VERSION 5.8 ;
BUSBITCHARS "[]" ;
DIVIDERCHAR "/" ;
UNITS
    DATABASE MICRONS 1000 ;
END UNITS

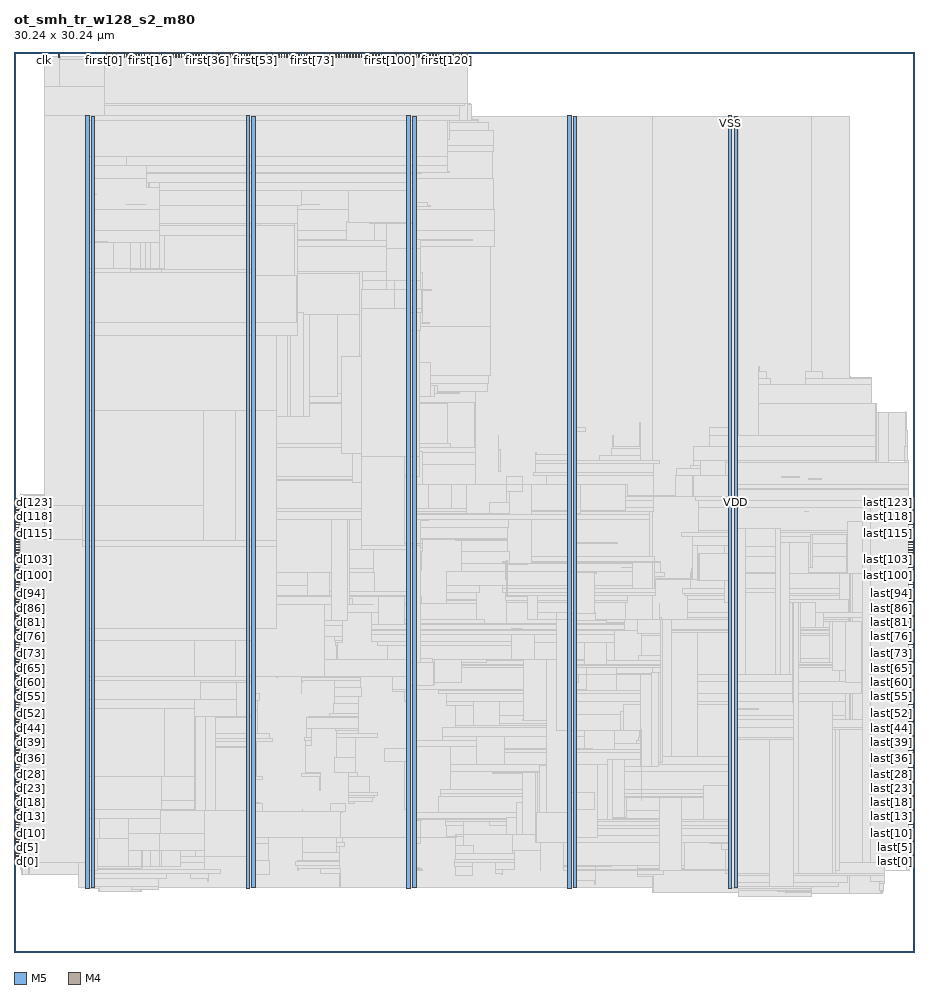
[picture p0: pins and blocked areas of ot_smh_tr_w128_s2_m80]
MACRO ot_smh_tr_w128_s2_m80
  FOREIGN ot_smh_tr_w128_s2_m80 0 0 ;
  CLASS BLOCK ;
  SIZE 30.24 BY 30.24 ;
  PIN clk
    DIRECTION INPUT ;
    USE SIGNAL ;
    PORT
      LAYER M5 ;
        RECT  1.008 30.048 1.032 30.24 ;
    END
  END clk
  PIN d[0]
    DIRECTION INPUT ;
    USE SIGNAL ;
    PORT
      LAYER M4 ;
        RECT  0 3.024 0.192 3.048 ;
    END
  END d[0]
  PIN d[100]
    DIRECTION INPUT ;
    USE SIGNAL ;
    PORT
      LAYER M4 ;
        RECT  0 12.624 0.192 12.648 ;
    END
  END d[100]
  PIN d[101]
    DIRECTION INPUT ;
    USE SIGNAL ;
    PORT
      LAYER M4 ;
        RECT  0 12.72 0.192 12.744 ;
    END
  END d[101]
  PIN d[102]
    DIRECTION INPUT ;
    USE SIGNAL ;
    PORT
      LAYER M4 ;
        RECT  0 12.816 0.192 12.84 ;
    END
  END d[102]
  PIN d[103]
    DIRECTION INPUT ;
    USE SIGNAL ;
    PORT
      LAYER M4 ;
        RECT  0 12.912 0.192 12.936 ;
    END
  END d[103]
  PIN d[104]
    DIRECTION INPUT ;
    USE SIGNAL ;
    PORT
      LAYER M4 ;
        RECT  0 13.008 0.192 13.032 ;
    END
  END d[104]
  PIN d[105]
    DIRECTION INPUT ;
    USE SIGNAL ;
    PORT
      LAYER M4 ;
        RECT  0 13.104 0.192 13.128 ;
    END
  END d[105]
  PIN d[106]
    DIRECTION INPUT ;
    USE SIGNAL ;
    PORT
      LAYER M4 ;
        RECT  0 13.2 0.192 13.224 ;
    END
  END d[106]
  PIN d[107]
    DIRECTION INPUT ;
    USE SIGNAL ;
    PORT
      LAYER M4 ;
        RECT  0 13.296 0.192 13.32 ;
    END
  END d[107]
  PIN d[108]
    DIRECTION INPUT ;
    USE SIGNAL ;
    PORT
      LAYER M4 ;
        RECT  0 13.392 0.192 13.416 ;
    END
  END d[108]
  PIN d[109]
    DIRECTION INPUT ;
    USE SIGNAL ;
    PORT
      LAYER M4 ;
        RECT  0 13.488 0.192 13.512 ;
    END
  END d[109]
  PIN d[10]
    DIRECTION INPUT ;
    USE SIGNAL ;
    PORT
      LAYER M4 ;
        RECT  0 3.984 0.192 4.008 ;
    END
  END d[10]
  PIN d[110]
    DIRECTION INPUT ;
    USE SIGNAL ;
    PORT
      LAYER M4 ;
        RECT  0 13.584 0.192 13.608 ;
    END
  END d[110]
  PIN d[111]
    DIRECTION INPUT ;
    USE SIGNAL ;
    PORT
      LAYER M4 ;
        RECT  0 13.68 0.192 13.704 ;
    END
  END d[111]
  PIN d[112]
    DIRECTION INPUT ;
    USE SIGNAL ;
    PORT
      LAYER M4 ;
        RECT  0 13.776 0.192 13.8 ;
    END
  END d[112]
  PIN d[113]
    DIRECTION INPUT ;
    USE SIGNAL ;
    PORT
      LAYER M4 ;
        RECT  0 13.872 0.192 13.896 ;
    END
  END d[113]
  PIN d[114]
    DIRECTION INPUT ;
    USE SIGNAL ;
    PORT
      LAYER M4 ;
        RECT  0 13.968 0.192 13.992 ;
    END
  END d[114]
  PIN d[115]
    DIRECTION INPUT ;
    USE SIGNAL ;
    PORT
      LAYER M4 ;
        RECT  0 14.064 0.192 14.088 ;
    END
  END d[115]
  PIN d[116]
    DIRECTION INPUT ;
    USE SIGNAL ;
    PORT
      LAYER M4 ;
        RECT  0 14.16 0.192 14.184 ;
    END
  END d[116]
  PIN d[117]
    DIRECTION INPUT ;
    USE SIGNAL ;
    PORT
      LAYER M4 ;
        RECT  0 14.256 0.192 14.28 ;
    END
  END d[117]
  PIN d[118]
    DIRECTION INPUT ;
    USE SIGNAL ;
    PORT
      LAYER M4 ;
        RECT  0 14.352 0.192 14.376 ;
    END
  END d[118]
  PIN d[119]
    DIRECTION INPUT ;
    USE SIGNAL ;
    PORT
      LAYER M4 ;
        RECT  0 14.448 0.192 14.472 ;
    END
  END d[119]
  PIN d[11]
    DIRECTION INPUT ;
    USE SIGNAL ;
    PORT
      LAYER M4 ;
        RECT  0 4.08 0.192 4.104 ;
    END
  END d[11]
  PIN d[120]
    DIRECTION INPUT ;
    USE SIGNAL ;
    PORT
      LAYER M4 ;
        RECT  0 14.544 0.192 14.568 ;
    END
  END d[120]
  PIN d[121]
    DIRECTION INPUT ;
    USE SIGNAL ;
    PORT
      LAYER M4 ;
        RECT  0 14.64 0.192 14.664 ;
    END
  END d[121]
  PIN d[122]
    DIRECTION INPUT ;
    USE SIGNAL ;
    PORT
      LAYER M4 ;
        RECT  0 14.736 0.192 14.76 ;
    END
  END d[122]
  PIN d[123]
    DIRECTION INPUT ;
    USE SIGNAL ;
    PORT
      LAYER M4 ;
        RECT  0 14.832 0.192 14.856 ;
    END
  END d[123]
  PIN d[124]
    DIRECTION INPUT ;
    USE SIGNAL ;
    PORT
      LAYER M4 ;
        RECT  0 14.928 0.192 14.952 ;
    END
  END d[124]
  PIN d[125]
    DIRECTION INPUT ;
    USE SIGNAL ;
    PORT
      LAYER M4 ;
        RECT  0 15.024 0.192 15.048 ;
    END
  END d[125]
  PIN d[126]
    DIRECTION INPUT ;
    USE SIGNAL ;
    PORT
      LAYER M4 ;
        RECT  0 15.12 0.192 15.144 ;
    END
  END d[126]
  PIN d[127]
    DIRECTION INPUT ;
    USE SIGNAL ;
    PORT
      LAYER M4 ;
        RECT  0 15.216 0.192 15.24 ;
    END
  END d[127]
  PIN d[12]
    DIRECTION INPUT ;
    USE SIGNAL ;
    PORT
      LAYER M4 ;
        RECT  0 4.176 0.192 4.2 ;
    END
  END d[12]
  PIN d[13]
    DIRECTION INPUT ;
    USE SIGNAL ;
    PORT
      LAYER M4 ;
        RECT  0 4.272 0.192 4.296 ;
    END
  END d[13]
  PIN d[14]
    DIRECTION INPUT ;
    USE SIGNAL ;
    PORT
      LAYER M4 ;
        RECT  0 4.368 0.192 4.392 ;
    END
  END d[14]
  PIN d[15]
    DIRECTION INPUT ;
    USE SIGNAL ;
    PORT
      LAYER M4 ;
        RECT  0 4.464 0.192 4.488 ;
    END
  END d[15]
  PIN d[16]
    DIRECTION INPUT ;
    USE SIGNAL ;
    PORT
      LAYER M4 ;
        RECT  0 4.56 0.192 4.584 ;
    END
  END d[16]
  PIN d[17]
    DIRECTION INPUT ;
    USE SIGNAL ;
    PORT
      LAYER M4 ;
        RECT  0 4.656 0.192 4.68 ;
    END
  END d[17]
  PIN d[18]
    DIRECTION INPUT ;
    USE SIGNAL ;
    PORT
      LAYER M4 ;
        RECT  0 4.752 0.192 4.776 ;
    END
  END d[18]
  PIN d[19]
    DIRECTION INPUT ;
    USE SIGNAL ;
    PORT
      LAYER M4 ;
        RECT  0 4.848 0.192 4.872 ;
    END
  END d[19]
  PIN d[1]
    DIRECTION INPUT ;
    USE SIGNAL ;
    PORT
      LAYER M4 ;
        RECT  0 3.12 0.192 3.144 ;
    END
  END d[1]
  PIN d[20]
    DIRECTION INPUT ;
    USE SIGNAL ;
    PORT
      LAYER M4 ;
        RECT  0 4.944 0.192 4.968 ;
    END
  END d[20]
  PIN d[21]
    DIRECTION INPUT ;
    USE SIGNAL ;
    PORT
      LAYER M4 ;
        RECT  0 5.04 0.192 5.064 ;
    END
  END d[21]
  PIN d[22]
    DIRECTION INPUT ;
    USE SIGNAL ;
    PORT
      LAYER M4 ;
        RECT  0 5.136 0.192 5.16 ;
    END
  END d[22]
  PIN d[23]
    DIRECTION INPUT ;
    USE SIGNAL ;
    PORT
      LAYER M4 ;
        RECT  0 5.232 0.192 5.256 ;
    END
  END d[23]
  PIN d[24]
    DIRECTION INPUT ;
    USE SIGNAL ;
    PORT
      LAYER M4 ;
        RECT  0 5.328 0.192 5.352 ;
    END
  END d[24]
  PIN d[25]
    DIRECTION INPUT ;
    USE SIGNAL ;
    PORT
      LAYER M4 ;
        RECT  0 5.424 0.192 5.448 ;
    END
  END d[25]
  PIN d[26]
    DIRECTION INPUT ;
    USE SIGNAL ;
    PORT
      LAYER M4 ;
        RECT  0 5.52 0.192 5.544 ;
    END
  END d[26]
  PIN d[27]
    DIRECTION INPUT ;
    USE SIGNAL ;
    PORT
      LAYER M4 ;
        RECT  0 5.616 0.192 5.64 ;
    END
  END d[27]
  PIN d[28]
    DIRECTION INPUT ;
    USE SIGNAL ;
    PORT
      LAYER M4 ;
        RECT  0 5.712 0.192 5.736 ;
    END
  END d[28]
  PIN d[29]
    DIRECTION INPUT ;
    USE SIGNAL ;
    PORT
      LAYER M4 ;
        RECT  0 5.808 0.192 5.832 ;
    END
  END d[29]
  PIN d[2]
    DIRECTION INPUT ;
    USE SIGNAL ;
    PORT
      LAYER M4 ;
        RECT  0 3.216 0.192 3.24 ;
    END
  END d[2]
  PIN d[30]
    DIRECTION INPUT ;
    USE SIGNAL ;
    PORT
      LAYER M4 ;
        RECT  0 5.904 0.192 5.928 ;
    END
  END d[30]
  PIN d[31]
    DIRECTION INPUT ;
    USE SIGNAL ;
    PORT
      LAYER M4 ;
        RECT  0 6 0.192 6.024 ;
    END
  END d[31]
  PIN d[32]
    DIRECTION INPUT ;
    USE SIGNAL ;
    PORT
      LAYER M4 ;
        RECT  0 6.096 0.192 6.12 ;
    END
  END d[32]
  PIN d[33]
    DIRECTION INPUT ;
    USE SIGNAL ;
    PORT
      LAYER M4 ;
        RECT  0 6.192 0.192 6.216 ;
    END
  END d[33]
  PIN d[34]
    DIRECTION INPUT ;
    USE SIGNAL ;
    PORT
      LAYER M4 ;
        RECT  0 6.288 0.192 6.312 ;
    END
  END d[34]
  PIN d[35]
    DIRECTION INPUT ;
    USE SIGNAL ;
    PORT
      LAYER M4 ;
        RECT  0 6.384 0.192 6.408 ;
    END
  END d[35]
  PIN d[36]
    DIRECTION INPUT ;
    USE SIGNAL ;
    PORT
      LAYER M4 ;
        RECT  0 6.48 0.192 6.504 ;
    END
  END d[36]
  PIN d[37]
    DIRECTION INPUT ;
    USE SIGNAL ;
    PORT
      LAYER M4 ;
        RECT  0 6.576 0.192 6.6 ;
    END
  END d[37]
  PIN d[38]
    DIRECTION INPUT ;
    USE SIGNAL ;
    PORT
      LAYER M4 ;
        RECT  0 6.672 0.192 6.696 ;
    END
  END d[38]
  PIN d[39]
    DIRECTION INPUT ;
    USE SIGNAL ;
    PORT
      LAYER M4 ;
        RECT  0 6.768 0.192 6.792 ;
    END
  END d[39]
  PIN d[3]
    DIRECTION INPUT ;
    USE SIGNAL ;
    PORT
      LAYER M4 ;
        RECT  0 3.312 0.192 3.336 ;
    END
  END d[3]
  PIN d[40]
    DIRECTION INPUT ;
    USE SIGNAL ;
    PORT
      LAYER M4 ;
        RECT  0 6.864 0.192 6.888 ;
    END
  END d[40]
  PIN d[41]
    DIRECTION INPUT ;
    USE SIGNAL ;
    PORT
      LAYER M4 ;
        RECT  0 6.96 0.192 6.984 ;
    END
  END d[41]
  PIN d[42]
    DIRECTION INPUT ;
    USE SIGNAL ;
    PORT
      LAYER M4 ;
        RECT  0 7.056 0.192 7.08 ;
    END
  END d[42]
  PIN d[43]
    DIRECTION INPUT ;
    USE SIGNAL ;
    PORT
      LAYER M4 ;
        RECT  0 7.152 0.192 7.176 ;
    END
  END d[43]
  PIN d[44]
    DIRECTION INPUT ;
    USE SIGNAL ;
    PORT
      LAYER M4 ;
        RECT  0 7.248 0.192 7.272 ;
    END
  END d[44]
  PIN d[45]
    DIRECTION INPUT ;
    USE SIGNAL ;
    PORT
      LAYER M4 ;
        RECT  0 7.344 0.192 7.368 ;
    END
  END d[45]
  PIN d[46]
    DIRECTION INPUT ;
    USE SIGNAL ;
    PORT
      LAYER M4 ;
        RECT  0 7.44 0.192 7.464 ;
    END
  END d[46]
  PIN d[47]
    DIRECTION INPUT ;
    USE SIGNAL ;
    PORT
      LAYER M4 ;
        RECT  0 7.536 0.192 7.56 ;
    END
  END d[47]
  PIN d[48]
    DIRECTION INPUT ;
    USE SIGNAL ;
    PORT
      LAYER M4 ;
        RECT  0 7.632 0.192 7.656 ;
    END
  END d[48]
  PIN d[49]
    DIRECTION INPUT ;
    USE SIGNAL ;
    PORT
      LAYER M4 ;
        RECT  0 7.728 0.192 7.752 ;
    END
  END d[49]
  PIN d[4]
    DIRECTION INPUT ;
    USE SIGNAL ;
    PORT
      LAYER M4 ;
        RECT  0 3.408 0.192 3.432 ;
    END
  END d[4]
  PIN d[50]
    DIRECTION INPUT ;
    USE SIGNAL ;
    PORT
      LAYER M4 ;
        RECT  0 7.824 0.192 7.848 ;
    END
  END d[50]
  PIN d[51]
    DIRECTION INPUT ;
    USE SIGNAL ;
    PORT
      LAYER M4 ;
        RECT  0 7.92 0.192 7.944 ;
    END
  END d[51]
  PIN d[52]
    DIRECTION INPUT ;
    USE SIGNAL ;
    PORT
      LAYER M4 ;
        RECT  0 8.016 0.192 8.04 ;
    END
  END d[52]
  PIN d[53]
    DIRECTION INPUT ;
    USE SIGNAL ;
    PORT
      LAYER M4 ;
        RECT  0 8.112 0.192 8.136 ;
    END
  END d[53]
  PIN d[54]
    DIRECTION INPUT ;
    USE SIGNAL ;
    PORT
      LAYER M4 ;
        RECT  0 8.208 0.192 8.232 ;
    END
  END d[54]
  PIN d[55]
    DIRECTION INPUT ;
    USE SIGNAL ;
    PORT
      LAYER M4 ;
        RECT  0 8.304 0.192 8.328 ;
    END
  END d[55]
  PIN d[56]
    DIRECTION INPUT ;
    USE SIGNAL ;
    PORT
      LAYER M4 ;
        RECT  0 8.4 0.192 8.424 ;
    END
  END d[56]
  PIN d[57]
    DIRECTION INPUT ;
    USE SIGNAL ;
    PORT
      LAYER M4 ;
        RECT  0 8.496 0.192 8.52 ;
    END
  END d[57]
  PIN d[58]
    DIRECTION INPUT ;
    USE SIGNAL ;
    PORT
      LAYER M4 ;
        RECT  0 8.592 0.192 8.616 ;
    END
  END d[58]
  PIN d[59]
    DIRECTION INPUT ;
    USE SIGNAL ;
    PORT
      LAYER M4 ;
        RECT  0 8.688 0.192 8.712 ;
    END
  END d[59]
  PIN d[5]
    DIRECTION INPUT ;
    USE SIGNAL ;
    PORT
      LAYER M4 ;
        RECT  0 3.504 0.192 3.528 ;
    END
  END d[5]
  PIN d[60]
    DIRECTION INPUT ;
    USE SIGNAL ;
    PORT
      LAYER M4 ;
        RECT  0 8.784 0.192 8.808 ;
    END
  END d[60]
  PIN d[61]
    DIRECTION INPUT ;
    USE SIGNAL ;
    PORT
      LAYER M4 ;
        RECT  0 8.88 0.192 8.904 ;
    END
  END d[61]
  PIN d[62]
    DIRECTION INPUT ;
    USE SIGNAL ;
    PORT
      LAYER M4 ;
        RECT  0 8.976 0.192 9 ;
    END
  END d[62]
  PIN d[63]
    DIRECTION INPUT ;
    USE SIGNAL ;
    PORT
      LAYER M4 ;
        RECT  0 9.072 0.192 9.096 ;
    END
  END d[63]
  PIN d[64]
    DIRECTION INPUT ;
    USE SIGNAL ;
    PORT
      LAYER M4 ;
        RECT  0 9.168 0.192 9.192 ;
    END
  END d[64]
  PIN d[65]
    DIRECTION INPUT ;
    USE SIGNAL ;
    PORT
      LAYER M4 ;
        RECT  0 9.264 0.192 9.288 ;
    END
  END d[65]
  PIN d[66]
    DIRECTION INPUT ;
    USE SIGNAL ;
    PORT
      LAYER M4 ;
        RECT  0 9.36 0.192 9.384 ;
    END
  END d[66]
  PIN d[67]
    DIRECTION INPUT ;
    USE SIGNAL ;
    PORT
      LAYER M4 ;
        RECT  0 9.456 0.192 9.48 ;
    END
  END d[67]
  PIN d[68]
    DIRECTION INPUT ;
    USE SIGNAL ;
    PORT
      LAYER M4 ;
        RECT  0 9.552 0.192 9.576 ;
    END
  END d[68]
  PIN d[69]
    DIRECTION INPUT ;
    USE SIGNAL ;
    PORT
      LAYER M4 ;
        RECT  0 9.648 0.192 9.672 ;
    END
  END d[69]
  PIN d[6]
    DIRECTION INPUT ;
    USE SIGNAL ;
    PORT
      LAYER M4 ;
        RECT  0 3.6 0.192 3.624 ;
    END
  END d[6]
  PIN d[70]
    DIRECTION INPUT ;
    USE SIGNAL ;
    PORT
      LAYER M4 ;
        RECT  0 9.744 0.192 9.768 ;
    END
  END d[70]
  PIN d[71]
    DIRECTION INPUT ;
    USE SIGNAL ;
    PORT
      LAYER M4 ;
        RECT  0 9.84 0.192 9.864 ;
    END
  END d[71]
  PIN d[72]
    DIRECTION INPUT ;
    USE SIGNAL ;
    PORT
      LAYER M4 ;
        RECT  0 9.936 0.192 9.96 ;
    END
  END d[72]
  PIN d[73]
    DIRECTION INPUT ;
    USE SIGNAL ;
    PORT
      LAYER M4 ;
        RECT  0 10.032 0.192 10.056 ;
    END
  END d[73]
  PIN d[74]
    DIRECTION INPUT ;
    USE SIGNAL ;
    PORT
      LAYER M4 ;
        RECT  0 10.128 0.192 10.152 ;
    END
  END d[74]
  PIN d[75]
    DIRECTION INPUT ;
    USE SIGNAL ;
    PORT
      LAYER M4 ;
        RECT  0 10.224 0.192 10.248 ;
    END
  END d[75]
  PIN d[76]
    DIRECTION INPUT ;
    USE SIGNAL ;
    PORT
      LAYER M4 ;
        RECT  0 10.32 0.192 10.344 ;
    END
  END d[76]
  PIN d[77]
    DIRECTION INPUT ;
    USE SIGNAL ;
    PORT
      LAYER M4 ;
        RECT  0 10.416 0.192 10.44 ;
    END
  END d[77]
  PIN d[78]
    DIRECTION INPUT ;
    USE SIGNAL ;
    PORT
      LAYER M4 ;
        RECT  0 10.512 0.192 10.536 ;
    END
  END d[78]
  PIN d[79]
    DIRECTION INPUT ;
    USE SIGNAL ;
    PORT
      LAYER M4 ;
        RECT  0 10.608 0.192 10.632 ;
    END
  END d[79]
  PIN d[7]
    DIRECTION INPUT ;
    USE SIGNAL ;
    PORT
      LAYER M4 ;
        RECT  0 3.696 0.192 3.72 ;
    END
  END d[7]
  PIN d[80]
    DIRECTION INPUT ;
    USE SIGNAL ;
    PORT
      LAYER M4 ;
        RECT  0 10.704 0.192 10.728 ;
    END
  END d[80]
  PIN d[81]
    DIRECTION INPUT ;
    USE SIGNAL ;
    PORT
      LAYER M4 ;
        RECT  0 10.8 0.192 10.824 ;
    END
  END d[81]
  PIN d[82]
    DIRECTION INPUT ;
    USE SIGNAL ;
    PORT
      LAYER M4 ;
        RECT  0 10.896 0.192 10.92 ;
    END
  END d[82]
  PIN d[83]
    DIRECTION INPUT ;
    USE SIGNAL ;
    PORT
      LAYER M4 ;
        RECT  0 10.992 0.192 11.016 ;
    END
  END d[83]
  PIN d[84]
    DIRECTION INPUT ;
    USE SIGNAL ;
    PORT
      LAYER M4 ;
        RECT  0 11.088 0.192 11.112 ;
    END
  END d[84]
  PIN d[85]
    DIRECTION INPUT ;
    USE SIGNAL ;
    PORT
      LAYER M4 ;
        RECT  0 11.184 0.192 11.208 ;
    END
  END d[85]
  PIN d[86]
    DIRECTION INPUT ;
    USE SIGNAL ;
    PORT
      LAYER M4 ;
        RECT  0 11.28 0.192 11.304 ;
    END
  END d[86]
  PIN d[87]
    DIRECTION INPUT ;
    USE SIGNAL ;
    PORT
      LAYER M4 ;
        RECT  0 11.376 0.192 11.4 ;
    END
  END d[87]
  PIN d[88]
    DIRECTION INPUT ;
    USE SIGNAL ;
    PORT
      LAYER M4 ;
        RECT  0 11.472 0.192 11.496 ;
    END
  END d[88]
  PIN d[89]
    DIRECTION INPUT ;
    USE SIGNAL ;
    PORT
      LAYER M4 ;
        RECT  0 11.568 0.192 11.592 ;
    END
  END d[89]
  PIN d[8]
    DIRECTION INPUT ;
    USE SIGNAL ;
    PORT
      LAYER M4 ;
        RECT  0 3.792 0.192 3.816 ;
    END
  END d[8]
  PIN d[90]
    DIRECTION INPUT ;
    USE SIGNAL ;
    PORT
      LAYER M4 ;
        RECT  0 11.664 0.192 11.688 ;
    END
  END d[90]
  PIN d[91]
    DIRECTION INPUT ;
    USE SIGNAL ;
    PORT
      LAYER M4 ;
        RECT  0 11.76 0.192 11.784 ;
    END
  END d[91]
  PIN d[92]
    DIRECTION INPUT ;
    USE SIGNAL ;
    PORT
      LAYER M4 ;
        RECT  0 11.856 0.192 11.88 ;
    END
  END d[92]
  PIN d[93]
    DIRECTION INPUT ;
    USE SIGNAL ;
    PORT
      LAYER M4 ;
        RECT  0 11.952 0.192 11.976 ;
    END
  END d[93]
  PIN d[94]
    DIRECTION INPUT ;
    USE SIGNAL ;
    PORT
      LAYER M4 ;
        RECT  0 12.048 0.192 12.072 ;
    END
  END d[94]
  PIN d[95]
    DIRECTION INPUT ;
    USE SIGNAL ;
    PORT
      LAYER M4 ;
        RECT  0 12.144 0.192 12.168 ;
    END
  END d[95]
  PIN d[96]
    DIRECTION INPUT ;
    USE SIGNAL ;
    PORT
      LAYER M4 ;
        RECT  0 12.24 0.192 12.264 ;
    END
  END d[96]
  PIN d[97]
    DIRECTION INPUT ;
    USE SIGNAL ;
    PORT
      LAYER M4 ;
        RECT  0 12.336 0.192 12.36 ;
    END
  END d[97]
  PIN d[98]
    DIRECTION INPUT ;
    USE SIGNAL ;
    PORT
      LAYER M4 ;
        RECT  0 12.432 0.192 12.456 ;
    END
  END d[98]
  PIN d[99]
    DIRECTION INPUT ;
    USE SIGNAL ;
    PORT
      LAYER M4 ;
        RECT  0 12.528 0.192 12.552 ;
    END
  END d[99]
  PIN d[9]
    DIRECTION INPUT ;
    USE SIGNAL ;
    PORT
      LAYER M4 ;
        RECT  0 3.888 0.192 3.912 ;
    END
  END d[9]
  PIN first[0]
    DIRECTION OUTPUT ;
    USE SIGNAL ;
    PORT
      LAYER M5 ;
        RECT  3.024 30.048 3.048 30.24 ;
    END
  END first[0]
  PIN first[100]
    DIRECTION OUTPUT ;
    USE SIGNAL ;
    PORT
      LAYER M5 ;
        RECT  12.624 30.048 12.648 30.24 ;
    END
  END first[100]
  PIN first[101]
    DIRECTION OUTPUT ;
    USE SIGNAL ;
    PORT
      LAYER M5 ;
        RECT  12.72 30.048 12.744 30.24 ;
    END
  END first[101]
  PIN first[102]
    DIRECTION OUTPUT ;
    USE SIGNAL ;
    PORT
      LAYER M5 ;
        RECT  12.816 30.048 12.84 30.24 ;
    END
  END first[102]
  PIN first[103]
    DIRECTION OUTPUT ;
    USE SIGNAL ;
    PORT
      LAYER M5 ;
        RECT  12.912 30.048 12.936 30.24 ;
    END
  END first[103]
  PIN first[104]
    DIRECTION OUTPUT ;
    USE SIGNAL ;
    PORT
      LAYER M5 ;
        RECT  13.008 30.048 13.032 30.24 ;
    END
  END first[104]
  PIN first[105]
    DIRECTION OUTPUT ;
    USE SIGNAL ;
    PORT
      LAYER M5 ;
        RECT  13.104 30.048 13.128 30.24 ;
    END
  END first[105]
  PIN first[106]
    DIRECTION OUTPUT ;
    USE SIGNAL ;
    PORT
      LAYER M5 ;
        RECT  13.2 30.048 13.224 30.24 ;
    END
  END first[106]
  PIN first[107]
    DIRECTION OUTPUT ;
    USE SIGNAL ;
    PORT
      LAYER M5 ;
        RECT  13.296 30.048 13.32 30.24 ;
    END
  END first[107]
  PIN first[108]
    DIRECTION OUTPUT ;
    USE SIGNAL ;
    PORT
      LAYER M5 ;
        RECT  13.392 30.048 13.416 30.24 ;
    END
  END first[108]
  PIN first[109]
    DIRECTION OUTPUT ;
    USE SIGNAL ;
    PORT
      LAYER M5 ;
        RECT  13.488 30.048 13.512 30.24 ;
    END
  END first[109]
  PIN first[10]
    DIRECTION OUTPUT ;
    USE SIGNAL ;
    PORT
      LAYER M5 ;
        RECT  3.984 30.048 4.008 30.24 ;
    END
  END first[10]
  PIN first[110]
    DIRECTION OUTPUT ;
    USE SIGNAL ;
    PORT
      LAYER M5 ;
        RECT  13.584 30.048 13.608 30.24 ;
    END
  END first[110]
  PIN first[111]
    DIRECTION OUTPUT ;
    USE SIGNAL ;
    PORT
      LAYER M5 ;
        RECT  13.68 30.048 13.704 30.24 ;
    END
  END first[111]
  PIN first[112]
    DIRECTION OUTPUT ;
    USE SIGNAL ;
    PORT
      LAYER M5 ;
        RECT  13.776 30.048 13.8 30.24 ;
    END
  END first[112]
  PIN first[113]
    DIRECTION OUTPUT ;
    USE SIGNAL ;
    PORT
      LAYER M5 ;
        RECT  13.872 30.048 13.896 30.24 ;
    END
  END first[113]
  PIN first[114]
    DIRECTION OUTPUT ;
    USE SIGNAL ;
    PORT
      LAYER M5 ;
        RECT  13.968 30.048 13.992 30.24 ;
    END
  END first[114]
  PIN first[115]
    DIRECTION OUTPUT ;
    USE SIGNAL ;
    PORT
      LAYER M5 ;
        RECT  14.064 30.048 14.088 30.24 ;
    END
  END first[115]
  PIN first[116]
    DIRECTION OUTPUT ;
    USE SIGNAL ;
    PORT
      LAYER M5 ;
        RECT  14.16 30.048 14.184 30.24 ;
    END
  END first[116]
  PIN first[117]
    DIRECTION OUTPUT ;
    USE SIGNAL ;
    PORT
      LAYER M5 ;
        RECT  14.256 30.048 14.28 30.24 ;
    END
  END first[117]
  PIN first[118]
    DIRECTION OUTPUT ;
    USE SIGNAL ;
    PORT
      LAYER M5 ;
        RECT  14.352 30.048 14.376 30.24 ;
    END
  END first[118]
  PIN first[119]
    DIRECTION OUTPUT ;
    USE SIGNAL ;
    PORT
      LAYER M5 ;
        RECT  14.448 30.048 14.472 30.24 ;
    END
  END first[119]
  PIN first[11]
    DIRECTION OUTPUT ;
    USE SIGNAL ;
    PORT
      LAYER M5 ;
        RECT  4.08 30.048 4.104 30.24 ;
    END
  END first[11]
  PIN first[120]
    DIRECTION OUTPUT ;
    USE SIGNAL ;
    PORT
      LAYER M5 ;
        RECT  14.544 30.048 14.568 30.24 ;
    END
  END first[120]
  PIN first[121]
    DIRECTION OUTPUT ;
    USE SIGNAL ;
    PORT
      LAYER M5 ;
        RECT  14.64 30.048 14.664 30.24 ;
    END
  END first[121]
  PIN first[122]
    DIRECTION OUTPUT ;
    USE SIGNAL ;
    PORT
      LAYER M5 ;
        RECT  14.736 30.048 14.76 30.24 ;
    END
  END first[122]
  PIN first[123]
    DIRECTION OUTPUT ;
    USE SIGNAL ;
    PORT
      LAYER M5 ;
        RECT  14.832 30.048 14.856 30.24 ;
    END
  END first[123]
  PIN first[124]
    DIRECTION OUTPUT ;
    USE SIGNAL ;
    PORT
      LAYER M5 ;
        RECT  14.928 30.048 14.952 30.24 ;
    END
  END first[124]
  PIN first[125]
    DIRECTION OUTPUT ;
    USE SIGNAL ;
    PORT
      LAYER M5 ;
        RECT  15.024 30.048 15.048 30.24 ;
    END
  END first[125]
  PIN first[126]
    DIRECTION OUTPUT ;
    USE SIGNAL ;
    PORT
      LAYER M5 ;
        RECT  15.12 30.048 15.144 30.24 ;
    END
  END first[126]
  PIN first[127]
    DIRECTION OUTPUT ;
    USE SIGNAL ;
    PORT
      LAYER M5 ;
        RECT  15.216 30.048 15.24 30.24 ;
    END
  END first[127]
  PIN first[12]
    DIRECTION OUTPUT ;
    USE SIGNAL ;
    PORT
      LAYER M5 ;
        RECT  4.176 30.048 4.2 30.24 ;
    END
  END first[12]
  PIN first[13]
    DIRECTION OUTPUT ;
    USE SIGNAL ;
    PORT
      LAYER M5 ;
        RECT  4.272 30.048 4.296 30.24 ;
    END
  END first[13]
  PIN first[14]
    DIRECTION OUTPUT ;
    USE SIGNAL ;
    PORT
      LAYER M5 ;
        RECT  4.368 30.048 4.392 30.24 ;
    END
  END first[14]
  PIN first[15]
    DIRECTION OUTPUT ;
    USE SIGNAL ;
    PORT
      LAYER M5 ;
        RECT  4.464 30.048 4.488 30.24 ;
    END
  END first[15]
  PIN first[16]
    DIRECTION OUTPUT ;
    USE SIGNAL ;
    PORT
      LAYER M5 ;
        RECT  4.56 30.048 4.584 30.24 ;
    END
  END first[16]
  PIN first[17]
    DIRECTION OUTPUT ;
    USE SIGNAL ;
    PORT
      LAYER M5 ;
        RECT  4.656 30.048 4.68 30.24 ;
    END
  END first[17]
  PIN first[18]
    DIRECTION OUTPUT ;
    USE SIGNAL ;
    PORT
      LAYER M5 ;
        RECT  4.752 30.048 4.776 30.24 ;
    END
  END first[18]
  PIN first[19]
    DIRECTION OUTPUT ;
    USE SIGNAL ;
    PORT
      LAYER M5 ;
        RECT  4.848 30.048 4.872 30.24 ;
    END
  END first[19]
  PIN first[1]
    DIRECTION OUTPUT ;
    USE SIGNAL ;
    PORT
      LAYER M5 ;
        RECT  3.12 30.048 3.144 30.24 ;
    END
  END first[1]
  PIN first[20]
    DIRECTION OUTPUT ;
    USE SIGNAL ;
    PORT
      LAYER M5 ;
        RECT  4.944 30.048 4.968 30.24 ;
    END
  END first[20]
  PIN first[21]
    DIRECTION OUTPUT ;
    USE SIGNAL ;
    PORT
      LAYER M5 ;
        RECT  5.04 30.048 5.064 30.24 ;
    END
  END first[21]
  PIN first[22]
    DIRECTION OUTPUT ;
    USE SIGNAL ;
    PORT
      LAYER M5 ;
        RECT  5.136 30.048 5.16 30.24 ;
    END
  END first[22]
  PIN first[23]
    DIRECTION OUTPUT ;
    USE SIGNAL ;
    PORT
      LAYER M5 ;
        RECT  5.232 30.048 5.256 30.24 ;
    END
  END first[23]
  PIN first[24]
    DIRECTION OUTPUT ;
    USE SIGNAL ;
    PORT
      LAYER M5 ;
        RECT  5.328 30.048 5.352 30.24 ;
    END
  END first[24]
  PIN first[25]
    DIRECTION OUTPUT ;
    USE SIGNAL ;
    PORT
      LAYER M5 ;
        RECT  5.424 30.048 5.448 30.24 ;
    END
  END first[25]
  PIN first[26]
    DIRECTION OUTPUT ;
    USE SIGNAL ;
    PORT
      LAYER M5 ;
        RECT  5.52 30.048 5.544 30.24 ;
    END
  END first[26]
  PIN first[27]
    DIRECTION OUTPUT ;
    USE SIGNAL ;
    PORT
      LAYER M5 ;
        RECT  5.616 30.048 5.64 30.24 ;
    END
  END first[27]
  PIN first[28]
    DIRECTION OUTPUT ;
    USE SIGNAL ;
    PORT
      LAYER M5 ;
        RECT  5.712 30.048 5.736 30.24 ;
    END
  END first[28]
  PIN first[29]
    DIRECTION OUTPUT ;
    USE SIGNAL ;
    PORT
      LAYER M5 ;
        RECT  5.808 30.048 5.832 30.24 ;
    END
  END first[29]
  PIN first[2]
    DIRECTION OUTPUT ;
    USE SIGNAL ;
    PORT
      LAYER M5 ;
        RECT  3.216 30.048 3.24 30.24 ;
    END
  END first[2]
  PIN first[30]
    DIRECTION OUTPUT ;
    USE SIGNAL ;
    PORT
      LAYER M5 ;
        RECT  5.904 30.048 5.928 30.24 ;
    END
  END first[30]
  PIN first[31]
    DIRECTION OUTPUT ;
    USE SIGNAL ;
    PORT
      LAYER M5 ;
        RECT  6 30.048 6.024 30.24 ;
    END
  END first[31]
  PIN first[32]
    DIRECTION OUTPUT ;
    USE SIGNAL ;
    PORT
      LAYER M5 ;
        RECT  6.096 30.048 6.12 30.24 ;
    END
  END first[32]
  PIN first[33]
    DIRECTION OUTPUT ;
    USE SIGNAL ;
    PORT
      LAYER M5 ;
        RECT  6.192 30.048 6.216 30.24 ;
    END
  END first[33]
  PIN first[34]
    DIRECTION OUTPUT ;
    USE SIGNAL ;
    PORT
      LAYER M5 ;
        RECT  6.288 30.048 6.312 30.24 ;
    END
  END first[34]
  PIN first[35]
    DIRECTION OUTPUT ;
    USE SIGNAL ;
    PORT
      LAYER M5 ;
        RECT  6.384 30.048 6.408 30.24 ;
    END
  END first[35]
  PIN first[36]
    DIRECTION OUTPUT ;
    USE SIGNAL ;
    PORT
      LAYER M5 ;
        RECT  6.48 30.048 6.504 30.24 ;
    END
  END first[36]
  PIN first[37]
    DIRECTION OUTPUT ;
    USE SIGNAL ;
    PORT
      LAYER M5 ;
        RECT  6.576 30.048 6.6 30.24 ;
    END
  END first[37]
  PIN first[38]
    DIRECTION OUTPUT ;
    USE SIGNAL ;
    PORT
      LAYER M5 ;
        RECT  6.672 30.048 6.696 30.24 ;
    END
  END first[38]
  PIN first[39]
    DIRECTION OUTPUT ;
    USE SIGNAL ;
    PORT
      LAYER M5 ;
        RECT  6.768 30.048 6.792 30.24 ;
    END
  END first[39]
  PIN first[3]
    DIRECTION OUTPUT ;
    USE SIGNAL ;
    PORT
      LAYER M5 ;
        RECT  3.312 30.048 3.336 30.24 ;
    END
  END first[3]
  PIN first[40]
    DIRECTION OUTPUT ;
    USE SIGNAL ;
    PORT
      LAYER M5 ;
        RECT  6.864 30.048 6.888 30.24 ;
    END
  END first[40]
  PIN first[41]
    DIRECTION OUTPUT ;
    USE SIGNAL ;
    PORT
      LAYER M5 ;
        RECT  6.96 30.048 6.984 30.24 ;
    END
  END first[41]
  PIN first[42]
    DIRECTION OUTPUT ;
    USE SIGNAL ;
    PORT
      LAYER M5 ;
        RECT  7.056 30.048 7.08 30.24 ;
    END
  END first[42]
  PIN first[43]
    DIRECTION OUTPUT ;
    USE SIGNAL ;
    PORT
      LAYER M5 ;
        RECT  7.152 30.048 7.176 30.24 ;
    END
  END first[43]
  PIN first[44]
    DIRECTION OUTPUT ;
    USE SIGNAL ;
    PORT
      LAYER M5 ;
        RECT  7.248 30.048 7.272 30.24 ;
    END
  END first[44]
  PIN first[45]
    DIRECTION OUTPUT ;
    USE SIGNAL ;
    PORT
      LAYER M5 ;
        RECT  7.344 30.048 7.368 30.24 ;
    END
  END first[45]
  PIN first[46]
    DIRECTION OUTPUT ;
    USE SIGNAL ;
    PORT
      LAYER M5 ;
        RECT  7.44 30.048 7.464 30.24 ;
    END
  END first[46]
  PIN first[47]
    DIRECTION OUTPUT ;
    USE SIGNAL ;
    PORT
      LAYER M5 ;
        RECT  7.536 30.048 7.56 30.24 ;
    END
  END first[47]
  PIN first[48]
    DIRECTION OUTPUT ;
    USE SIGNAL ;
    PORT
      LAYER M5 ;
        RECT  7.632 30.048 7.656 30.24 ;
    END
  END first[48]
  PIN first[49]
    DIRECTION OUTPUT ;
    USE SIGNAL ;
    PORT
      LAYER M5 ;
        RECT  7.728 30.048 7.752 30.24 ;
    END
  END first[49]
  PIN first[4]
    DIRECTION OUTPUT ;
    USE SIGNAL ;
    PORT
      LAYER M5 ;
        RECT  3.408 30.048 3.432 30.24 ;
    END
  END first[4]
  PIN first[50]
    DIRECTION OUTPUT ;
    USE SIGNAL ;
    PORT
      LAYER M5 ;
        RECT  7.824 30.048 7.848 30.24 ;
    END
  END first[50]
  PIN first[51]
    DIRECTION OUTPUT ;
    USE SIGNAL ;
    PORT
      LAYER M5 ;
        RECT  7.92 30.048 7.944 30.24 ;
    END
  END first[51]
  PIN first[52]
    DIRECTION OUTPUT ;
    USE SIGNAL ;
    PORT
      LAYER M5 ;
        RECT  8.016 30.048 8.04 30.24 ;
    END
  END first[52]
  PIN first[53]
    DIRECTION OUTPUT ;
    USE SIGNAL ;
    PORT
      LAYER M5 ;
        RECT  8.112 30.048 8.136 30.24 ;
    END
  END first[53]
  PIN first[54]
    DIRECTION OUTPUT ;
    USE SIGNAL ;
    PORT
      LAYER M5 ;
        RECT  8.208 30.048 8.232 30.24 ;
    END
  END first[54]
  PIN first[55]
    DIRECTION OUTPUT ;
    USE SIGNAL ;
    PORT
      LAYER M5 ;
        RECT  8.304 30.048 8.328 30.24 ;
    END
  END first[55]
  PIN first[56]
    DIRECTION OUTPUT ;
    USE SIGNAL ;
    PORT
      LAYER M5 ;
        RECT  8.4 30.048 8.424 30.24 ;
    END
  END first[56]
  PIN first[57]
    DIRECTION OUTPUT ;
    USE SIGNAL ;
    PORT
      LAYER M5 ;
        RECT  8.496 30.048 8.52 30.24 ;
    END
  END first[57]
  PIN first[58]
    DIRECTION OUTPUT ;
    USE SIGNAL ;
    PORT
      LAYER M5 ;
        RECT  8.592 30.048 8.616 30.24 ;
    END
  END first[58]
  PIN first[59]
    DIRECTION OUTPUT ;
    USE SIGNAL ;
    PORT
      LAYER M5 ;
        RECT  8.688 30.048 8.712 30.24 ;
    END
  END first[59]
  PIN first[5]
    DIRECTION OUTPUT ;
    USE SIGNAL ;
    PORT
      LAYER M5 ;
        RECT  3.504 30.048 3.528 30.24 ;
    END
  END first[5]
  PIN first[60]
    DIRECTION OUTPUT ;
    USE SIGNAL ;
    PORT
      LAYER M5 ;
        RECT  8.784 30.048 8.808 30.24 ;
    END
  END first[60]
  PIN first[61]
    DIRECTION OUTPUT ;
    USE SIGNAL ;
    PORT
      LAYER M5 ;
        RECT  8.88 30.048 8.904 30.24 ;
    END
  END first[61]
  PIN first[62]
    DIRECTION OUTPUT ;
    USE SIGNAL ;
    PORT
      LAYER M5 ;
        RECT  8.976 30.048 9 30.24 ;
    END
  END first[62]
  PIN first[63]
    DIRECTION OUTPUT ;
    USE SIGNAL ;
    PORT
      LAYER M5 ;
        RECT  9.072 30.048 9.096 30.24 ;
    END
  END first[63]
  PIN first[64]
    DIRECTION OUTPUT ;
    USE SIGNAL ;
    PORT
      LAYER M5 ;
        RECT  9.168 30.048 9.192 30.24 ;
    END
  END first[64]
  PIN first[65]
    DIRECTION OUTPUT ;
    USE SIGNAL ;
    PORT
      LAYER M5 ;
        RECT  9.264 30.048 9.288 30.24 ;
    END
  END first[65]
  PIN first[66]
    DIRECTION OUTPUT ;
    USE SIGNAL ;
    PORT
      LAYER M5 ;
        RECT  9.36 30.048 9.384 30.24 ;
    END
  END first[66]
  PIN first[67]
    DIRECTION OUTPUT ;
    USE SIGNAL ;
    PORT
      LAYER M5 ;
        RECT  9.456 30.048 9.48 30.24 ;
    END
  END first[67]
  PIN first[68]
    DIRECTION OUTPUT ;
    USE SIGNAL ;
    PORT
      LAYER M5 ;
        RECT  9.552 30.048 9.576 30.24 ;
    END
  END first[68]
  PIN first[69]
    DIRECTION OUTPUT ;
    USE SIGNAL ;
    PORT
      LAYER M5 ;
        RECT  9.648 30.048 9.672 30.24 ;
    END
  END first[69]
  PIN first[6]
    DIRECTION OUTPUT ;
    USE SIGNAL ;
    PORT
      LAYER M5 ;
        RECT  3.6 30.048 3.624 30.24 ;
    END
  END first[6]
  PIN first[70]
    DIRECTION OUTPUT ;
    USE SIGNAL ;
    PORT
      LAYER M5 ;
        RECT  9.744 30.048 9.768 30.24 ;
    END
  END first[70]
  PIN first[71]
    DIRECTION OUTPUT ;
    USE SIGNAL ;
    PORT
      LAYER M5 ;
        RECT  9.84 30.048 9.864 30.24 ;
    END
  END first[71]
  PIN first[72]
    DIRECTION OUTPUT ;
    USE SIGNAL ;
    PORT
      LAYER M5 ;
        RECT  9.936 30.048 9.96 30.24 ;
    END
  END first[72]
  PIN first[73]
    DIRECTION OUTPUT ;
    USE SIGNAL ;
    PORT
      LAYER M5 ;
        RECT  10.032 30.048 10.056 30.24 ;
    END
  END first[73]
  PIN first[74]
    DIRECTION OUTPUT ;
    USE SIGNAL ;
    PORT
      LAYER M5 ;
        RECT  10.128 30.048 10.152 30.24 ;
    END
  END first[74]
  PIN first[75]
    DIRECTION OUTPUT ;
    USE SIGNAL ;
    PORT
      LAYER M5 ;
        RECT  10.224 30.048 10.248 30.24 ;
    END
  END first[75]
  PIN first[76]
    DIRECTION OUTPUT ;
    USE SIGNAL ;
    PORT
      LAYER M5 ;
        RECT  10.32 30.048 10.344 30.24 ;
    END
  END first[76]
  PIN first[77]
    DIRECTION OUTPUT ;
    USE SIGNAL ;
    PORT
      LAYER M5 ;
        RECT  10.416 30.048 10.44 30.24 ;
    END
  END first[77]
  PIN first[78]
    DIRECTION OUTPUT ;
    USE SIGNAL ;
    PORT
      LAYER M5 ;
        RECT  10.512 30.048 10.536 30.24 ;
    END
  END first[78]
  PIN first[79]
    DIRECTION OUTPUT ;
    USE SIGNAL ;
    PORT
      LAYER M5 ;
        RECT  10.608 30.048 10.632 30.24 ;
    END
  END first[79]
  PIN first[7]
    DIRECTION OUTPUT ;
    USE SIGNAL ;
    PORT
      LAYER M5 ;
        RECT  3.696 30.048 3.72 30.24 ;
    END
  END first[7]
  PIN first[80]
    DIRECTION OUTPUT ;
    USE SIGNAL ;
    PORT
      LAYER M5 ;
        RECT  10.704 30.048 10.728 30.24 ;
    END
  END first[80]
  PIN first[81]
    DIRECTION OUTPUT ;
    USE SIGNAL ;
    PORT
      LAYER M5 ;
        RECT  10.8 30.048 10.824 30.24 ;
    END
  END first[81]
  PIN first[82]
    DIRECTION OUTPUT ;
    USE SIGNAL ;
    PORT
      LAYER M5 ;
        RECT  10.896 30.048 10.92 30.24 ;
    END
  END first[82]
  PIN first[83]
    DIRECTION OUTPUT ;
    USE SIGNAL ;
    PORT
      LAYER M5 ;
        RECT  10.992 30.048 11.016 30.24 ;
    END
  END first[83]
  PIN first[84]
    DIRECTION OUTPUT ;
    USE SIGNAL ;
    PORT
      LAYER M5 ;
        RECT  11.088 30.048 11.112 30.24 ;
    END
  END first[84]
  PIN first[85]
    DIRECTION OUTPUT ;
    USE SIGNAL ;
    PORT
      LAYER M5 ;
        RECT  11.184 30.048 11.208 30.24 ;
    END
  END first[85]
  PIN first[86]
    DIRECTION OUTPUT ;
    USE SIGNAL ;
    PORT
      LAYER M5 ;
        RECT  11.28 30.048 11.304 30.24 ;
    END
  END first[86]
  PIN first[87]
    DIRECTION OUTPUT ;
    USE SIGNAL ;
    PORT
      LAYER M5 ;
        RECT  11.376 30.048 11.4 30.24 ;
    END
  END first[87]
  PIN first[88]
    DIRECTION OUTPUT ;
    USE SIGNAL ;
    PORT
      LAYER M5 ;
        RECT  11.472 30.048 11.496 30.24 ;
    END
  END first[88]
  PIN first[89]
    DIRECTION OUTPUT ;
    USE SIGNAL ;
    PORT
      LAYER M5 ;
        RECT  11.568 30.048 11.592 30.24 ;
    END
  END first[89]
  PIN first[8]
    DIRECTION OUTPUT ;
    USE SIGNAL ;
    PORT
      LAYER M5 ;
        RECT  3.792 30.048 3.816 30.24 ;
    END
  END first[8]
  PIN first[90]
    DIRECTION OUTPUT ;
    USE SIGNAL ;
    PORT
      LAYER M5 ;
        RECT  11.664 30.048 11.688 30.24 ;
    END
  END first[90]
  PIN first[91]
    DIRECTION OUTPUT ;
    USE SIGNAL ;
    PORT
      LAYER M5 ;
        RECT  11.76 30.048 11.784 30.24 ;
    END
  END first[91]
  PIN first[92]
    DIRECTION OUTPUT ;
    USE SIGNAL ;
    PORT
      LAYER M5 ;
        RECT  11.856 30.048 11.88 30.24 ;
    END
  END first[92]
  PIN first[93]
    DIRECTION OUTPUT ;
    USE SIGNAL ;
    PORT
      LAYER M5 ;
        RECT  11.952 30.048 11.976 30.24 ;
    END
  END first[93]
  PIN first[94]
    DIRECTION OUTPUT ;
    USE SIGNAL ;
    PORT
      LAYER M5 ;
        RECT  12.048 30.048 12.072 30.24 ;
    END
  END first[94]
  PIN first[95]
    DIRECTION OUTPUT ;
    USE SIGNAL ;
    PORT
      LAYER M5 ;
        RECT  12.144 30.048 12.168 30.24 ;
    END
  END first[95]
  PIN first[96]
    DIRECTION OUTPUT ;
    USE SIGNAL ;
    PORT
      LAYER M5 ;
        RECT  12.24 30.048 12.264 30.24 ;
    END
  END first[96]
  PIN first[97]
    DIRECTION OUTPUT ;
    USE SIGNAL ;
    PORT
      LAYER M5 ;
        RECT  12.336 30.048 12.36 30.24 ;
    END
  END first[97]
  PIN first[98]
    DIRECTION OUTPUT ;
    USE SIGNAL ;
    PORT
      LAYER M5 ;
        RECT  12.432 30.048 12.456 30.24 ;
    END
  END first[98]
  PIN first[99]
    DIRECTION OUTPUT ;
    USE SIGNAL ;
    PORT
      LAYER M5 ;
        RECT  12.528 30.048 12.552 30.24 ;
    END
  END first[99]
  PIN first[9]
    DIRECTION OUTPUT ;
    USE SIGNAL ;
    PORT
      LAYER M5 ;
        RECT  3.888 30.048 3.912 30.24 ;
    END
  END first[9]
  PIN last[0]
    DIRECTION OUTPUT ;
    USE SIGNAL ;
    PORT
      LAYER M4 ;
        RECT  30.048 3.024 30.24 3.048 ;
    END
  END last[0]
  PIN last[100]
    DIRECTION OUTPUT ;
    USE SIGNAL ;
    PORT
      LAYER M4 ;
        RECT  30.048 12.624 30.24 12.648 ;
    END
  END last[100]
  PIN last[101]
    DIRECTION OUTPUT ;
    USE SIGNAL ;
    PORT
      LAYER M4 ;
        RECT  30.048 12.72 30.24 12.744 ;
    END
  END last[101]
  PIN last[102]
    DIRECTION OUTPUT ;
    USE SIGNAL ;
    PORT
      LAYER M4 ;
        RECT  30.048 12.816 30.24 12.84 ;
    END
  END last[102]
  PIN last[103]
    DIRECTION OUTPUT ;
    USE SIGNAL ;
    PORT
      LAYER M4 ;
        RECT  30.048 12.912 30.24 12.936 ;
    END
  END last[103]
  PIN last[104]
    DIRECTION OUTPUT ;
    USE SIGNAL ;
    PORT
      LAYER M4 ;
        RECT  30.048 13.008 30.24 13.032 ;
    END
  END last[104]
  PIN last[105]
    DIRECTION OUTPUT ;
    USE SIGNAL ;
    PORT
      LAYER M4 ;
        RECT  30.048 13.104 30.24 13.128 ;
    END
  END last[105]
  PIN last[106]
    DIRECTION OUTPUT ;
    USE SIGNAL ;
    PORT
      LAYER M4 ;
        RECT  30.048 13.2 30.24 13.224 ;
    END
  END last[106]
  PIN last[107]
    DIRECTION OUTPUT ;
    USE SIGNAL ;
    PORT
      LAYER M4 ;
        RECT  30.048 13.296 30.24 13.32 ;
    END
  END last[107]
  PIN last[108]
    DIRECTION OUTPUT ;
    USE SIGNAL ;
    PORT
      LAYER M4 ;
        RECT  30.048 13.392 30.24 13.416 ;
    END
  END last[108]
  PIN last[109]
    DIRECTION OUTPUT ;
    USE SIGNAL ;
    PORT
      LAYER M4 ;
        RECT  30.048 13.488 30.24 13.512 ;
    END
  END last[109]
  PIN last[10]
    DIRECTION OUTPUT ;
    USE SIGNAL ;
    PORT
      LAYER M4 ;
        RECT  30.048 3.984 30.24 4.008 ;
    END
  END last[10]
  PIN last[110]
    DIRECTION OUTPUT ;
    USE SIGNAL ;
    PORT
      LAYER M4 ;
        RECT  30.048 13.584 30.24 13.608 ;
    END
  END last[110]
  PIN last[111]
    DIRECTION OUTPUT ;
    USE SIGNAL ;
    PORT
      LAYER M4 ;
        RECT  30.048 13.68 30.24 13.704 ;
    END
  END last[111]
  PIN last[112]
    DIRECTION OUTPUT ;
    USE SIGNAL ;
    PORT
      LAYER M4 ;
        RECT  30.048 13.776 30.24 13.8 ;
    END
  END last[112]
  PIN last[113]
    DIRECTION OUTPUT ;
    USE SIGNAL ;
    PORT
      LAYER M4 ;
        RECT  30.048 13.872 30.24 13.896 ;
    END
  END last[113]
  PIN last[114]
    DIRECTION OUTPUT ;
    USE SIGNAL ;
    PORT
      LAYER M4 ;
        RECT  30.048 13.968 30.24 13.992 ;
    END
  END last[114]
  PIN last[115]
    DIRECTION OUTPUT ;
    USE SIGNAL ;
    PORT
      LAYER M4 ;
        RECT  30.048 14.064 30.24 14.088 ;
    END
  END last[115]
  PIN last[116]
    DIRECTION OUTPUT ;
    USE SIGNAL ;
    PORT
      LAYER M4 ;
        RECT  30.048 14.16 30.24 14.184 ;
    END
  END last[116]
  PIN last[117]
    DIRECTION OUTPUT ;
    USE SIGNAL ;
    PORT
      LAYER M4 ;
        RECT  30.048 14.256 30.24 14.28 ;
    END
  END last[117]
  PIN last[118]
    DIRECTION OUTPUT ;
    USE SIGNAL ;
    PORT
      LAYER M4 ;
        RECT  30.048 14.352 30.24 14.376 ;
    END
  END last[118]
  PIN last[119]
    DIRECTION OUTPUT ;
    USE SIGNAL ;
    PORT
      LAYER M4 ;
        RECT  30.048 14.448 30.24 14.472 ;
    END
  END last[119]
  PIN last[11]
    DIRECTION OUTPUT ;
    USE SIGNAL ;
    PORT
      LAYER M4 ;
        RECT  30.048 4.08 30.24 4.104 ;
    END
  END last[11]
  PIN last[120]
    DIRECTION OUTPUT ;
    USE SIGNAL ;
    PORT
      LAYER M4 ;
        RECT  30.048 14.544 30.24 14.568 ;
    END
  END last[120]
  PIN last[121]
    DIRECTION OUTPUT ;
    USE SIGNAL ;
    PORT
      LAYER M4 ;
        RECT  30.048 14.64 30.24 14.664 ;
    END
  END last[121]
  PIN last[122]
    DIRECTION OUTPUT ;
    USE SIGNAL ;
    PORT
      LAYER M4 ;
        RECT  30.048 14.736 30.24 14.76 ;
    END
  END last[122]
  PIN last[123]
    DIRECTION OUTPUT ;
    USE SIGNAL ;
    PORT
      LAYER M4 ;
        RECT  30.048 14.832 30.24 14.856 ;
    END
  END last[123]
  PIN last[124]
    DIRECTION OUTPUT ;
    USE SIGNAL ;
    PORT
      LAYER M4 ;
        RECT  30.048 14.928 30.24 14.952 ;
    END
  END last[124]
  PIN last[125]
    DIRECTION OUTPUT ;
    USE SIGNAL ;
    PORT
      LAYER M4 ;
        RECT  30.048 15.024 30.24 15.048 ;
    END
  END last[125]
  PIN last[126]
    DIRECTION OUTPUT ;
    USE SIGNAL ;
    PORT
      LAYER M4 ;
        RECT  30.048 15.12 30.24 15.144 ;
    END
  END last[126]
  PIN last[127]
    DIRECTION OUTPUT ;
    USE SIGNAL ;
    PORT
      LAYER M4 ;
        RECT  30.048 15.216 30.24 15.24 ;
    END
  END last[127]
  PIN last[12]
    DIRECTION OUTPUT ;
    USE SIGNAL ;
    PORT
      LAYER M4 ;
        RECT  30.048 4.176 30.24 4.2 ;
    END
  END last[12]
  PIN last[13]
    DIRECTION OUTPUT ;
    USE SIGNAL ;
    PORT
      LAYER M4 ;
        RECT  30.048 4.272 30.24 4.296 ;
    END
  END last[13]
  PIN last[14]
    DIRECTION OUTPUT ;
    USE SIGNAL ;
    PORT
      LAYER M4 ;
        RECT  30.048 4.368 30.24 4.392 ;
    END
  END last[14]
  PIN last[15]
    DIRECTION OUTPUT ;
    USE SIGNAL ;
    PORT
      LAYER M4 ;
        RECT  30.048 4.464 30.24 4.488 ;
    END
  END last[15]
  PIN last[16]
    DIRECTION OUTPUT ;
    USE SIGNAL ;
    PORT
      LAYER M4 ;
        RECT  30.048 4.56 30.24 4.584 ;
    END
  END last[16]
  PIN last[17]
    DIRECTION OUTPUT ;
    USE SIGNAL ;
    PORT
      LAYER M4 ;
        RECT  30.048 4.656 30.24 4.68 ;
    END
  END last[17]
  PIN last[18]
    DIRECTION OUTPUT ;
    USE SIGNAL ;
    PORT
      LAYER M4 ;
        RECT  30.048 4.752 30.24 4.776 ;
    END
  END last[18]
  PIN last[19]
    DIRECTION OUTPUT ;
    USE SIGNAL ;
    PORT
      LAYER M4 ;
        RECT  30.048 4.848 30.24 4.872 ;
    END
  END last[19]
  PIN last[1]
    DIRECTION OUTPUT ;
    USE SIGNAL ;
    PORT
      LAYER M4 ;
        RECT  30.048 3.12 30.24 3.144 ;
    END
  END last[1]
  PIN last[20]
    DIRECTION OUTPUT ;
    USE SIGNAL ;
    PORT
      LAYER M4 ;
        RECT  30.048 4.944 30.24 4.968 ;
    END
  END last[20]
  PIN last[21]
    DIRECTION OUTPUT ;
    USE SIGNAL ;
    PORT
      LAYER M4 ;
        RECT  30.048 5.04 30.24 5.064 ;
    END
  END last[21]
  PIN last[22]
    DIRECTION OUTPUT ;
    USE SIGNAL ;
    PORT
      LAYER M4 ;
        RECT  30.048 5.136 30.24 5.16 ;
    END
  END last[22]
  PIN last[23]
    DIRECTION OUTPUT ;
    USE SIGNAL ;
    PORT
      LAYER M4 ;
        RECT  30.048 5.232 30.24 5.256 ;
    END
  END last[23]
  PIN last[24]
    DIRECTION OUTPUT ;
    USE SIGNAL ;
    PORT
      LAYER M4 ;
        RECT  30.048 5.328 30.24 5.352 ;
    END
  END last[24]
  PIN last[25]
    DIRECTION OUTPUT ;
    USE SIGNAL ;
    PORT
      LAYER M4 ;
        RECT  30.048 5.424 30.24 5.448 ;
    END
  END last[25]
  PIN last[26]
    DIRECTION OUTPUT ;
    USE SIGNAL ;
    PORT
      LAYER M4 ;
        RECT  30.048 5.52 30.24 5.544 ;
    END
  END last[26]
  PIN last[27]
    DIRECTION OUTPUT ;
    USE SIGNAL ;
    PORT
      LAYER M4 ;
        RECT  30.048 5.616 30.24 5.64 ;
    END
  END last[27]
  PIN last[28]
    DIRECTION OUTPUT ;
    USE SIGNAL ;
    PORT
      LAYER M4 ;
        RECT  30.048 5.712 30.24 5.736 ;
    END
  END last[28]
  PIN last[29]
    DIRECTION OUTPUT ;
    USE SIGNAL ;
    PORT
      LAYER M4 ;
        RECT  30.048 5.808 30.24 5.832 ;
    END
  END last[29]
  PIN last[2]
    DIRECTION OUTPUT ;
    USE SIGNAL ;
    PORT
      LAYER M4 ;
        RECT  30.048 3.216 30.24 3.24 ;
    END
  END last[2]
  PIN last[30]
    DIRECTION OUTPUT ;
    USE SIGNAL ;
    PORT
      LAYER M4 ;
        RECT  30.048 5.904 30.24 5.928 ;
    END
  END last[30]
  PIN last[31]
    DIRECTION OUTPUT ;
    USE SIGNAL ;
    PORT
      LAYER M4 ;
        RECT  30.048 6 30.24 6.024 ;
    END
  END last[31]
  PIN last[32]
    DIRECTION OUTPUT ;
    USE SIGNAL ;
    PORT
      LAYER M4 ;
        RECT  30.048 6.096 30.24 6.12 ;
    END
  END last[32]
  PIN last[33]
    DIRECTION OUTPUT ;
    USE SIGNAL ;
    PORT
      LAYER M4 ;
        RECT  30.048 6.192 30.24 6.216 ;
    END
  END last[33]
  PIN last[34]
    DIRECTION OUTPUT ;
    USE SIGNAL ;
    PORT
      LAYER M4 ;
        RECT  30.048 6.288 30.24 6.312 ;
    END
  END last[34]
  PIN last[35]
    DIRECTION OUTPUT ;
    USE SIGNAL ;
    PORT
      LAYER M4 ;
        RECT  30.048 6.384 30.24 6.408 ;
    END
  END last[35]
  PIN last[36]
    DIRECTION OUTPUT ;
    USE SIGNAL ;
    PORT
      LAYER M4 ;
        RECT  30.048 6.48 30.24 6.504 ;
    END
  END last[36]
  PIN last[37]
    DIRECTION OUTPUT ;
    USE SIGNAL ;
    PORT
      LAYER M4 ;
        RECT  30.048 6.576 30.24 6.6 ;
    END
  END last[37]
  PIN last[38]
    DIRECTION OUTPUT ;
    USE SIGNAL ;
    PORT
      LAYER M4 ;
        RECT  30.048 6.672 30.24 6.696 ;
    END
  END last[38]
  PIN last[39]
    DIRECTION OUTPUT ;
    USE SIGNAL ;
    PORT
      LAYER M4 ;
        RECT  30.048 6.768 30.24 6.792 ;
    END
  END last[39]
  PIN last[3]
    DIRECTION OUTPUT ;
    USE SIGNAL ;
    PORT
      LAYER M4 ;
        RECT  30.048 3.312 30.24 3.336 ;
    END
  END last[3]
  PIN last[40]
    DIRECTION OUTPUT ;
    USE SIGNAL ;
    PORT
      LAYER M4 ;
        RECT  30.048 6.864 30.24 6.888 ;
    END
  END last[40]
  PIN last[41]
    DIRECTION OUTPUT ;
    USE SIGNAL ;
    PORT
      LAYER M4 ;
        RECT  30.048 6.96 30.24 6.984 ;
    END
  END last[41]
  PIN last[42]
    DIRECTION OUTPUT ;
    USE SIGNAL ;
    PORT
      LAYER M4 ;
        RECT  30.048 7.056 30.24 7.08 ;
    END
  END last[42]
  PIN last[43]
    DIRECTION OUTPUT ;
    USE SIGNAL ;
    PORT
      LAYER M4 ;
        RECT  30.048 7.152 30.24 7.176 ;
    END
  END last[43]
  PIN last[44]
    DIRECTION OUTPUT ;
    USE SIGNAL ;
    PORT
      LAYER M4 ;
        RECT  30.048 7.248 30.24 7.272 ;
    END
  END last[44]
  PIN last[45]
    DIRECTION OUTPUT ;
    USE SIGNAL ;
    PORT
      LAYER M4 ;
        RECT  30.048 7.344 30.24 7.368 ;
    END
  END last[45]
  PIN last[46]
    DIRECTION OUTPUT ;
    USE SIGNAL ;
    PORT
      LAYER M4 ;
        RECT  30.048 7.44 30.24 7.464 ;
    END
  END last[46]
  PIN last[47]
    DIRECTION OUTPUT ;
    USE SIGNAL ;
    PORT
      LAYER M4 ;
        RECT  30.048 7.536 30.24 7.56 ;
    END
  END last[47]
  PIN last[48]
    DIRECTION OUTPUT ;
    USE SIGNAL ;
    PORT
      LAYER M4 ;
        RECT  30.048 7.632 30.24 7.656 ;
    END
  END last[48]
  PIN last[49]
    DIRECTION OUTPUT ;
    USE SIGNAL ;
    PORT
      LAYER M4 ;
        RECT  30.048 7.728 30.24 7.752 ;
    END
  END last[49]
  PIN last[4]
    DIRECTION OUTPUT ;
    USE SIGNAL ;
    PORT
      LAYER M4 ;
        RECT  30.048 3.408 30.24 3.432 ;
    END
  END last[4]
  PIN last[50]
    DIRECTION OUTPUT ;
    USE SIGNAL ;
    PORT
      LAYER M4 ;
        RECT  30.048 7.824 30.24 7.848 ;
    END
  END last[50]
  PIN last[51]
    DIRECTION OUTPUT ;
    USE SIGNAL ;
    PORT
      LAYER M4 ;
        RECT  30.048 7.92 30.24 7.944 ;
    END
  END last[51]
  PIN last[52]
    DIRECTION OUTPUT ;
    USE SIGNAL ;
    PORT
      LAYER M4 ;
        RECT  30.048 8.016 30.24 8.04 ;
    END
  END last[52]
  PIN last[53]
    DIRECTION OUTPUT ;
    USE SIGNAL ;
    PORT
      LAYER M4 ;
        RECT  30.048 8.112 30.24 8.136 ;
    END
  END last[53]
  PIN last[54]
    DIRECTION OUTPUT ;
    USE SIGNAL ;
    PORT
      LAYER M4 ;
        RECT  30.048 8.208 30.24 8.232 ;
    END
  END last[54]
  PIN last[55]
    DIRECTION OUTPUT ;
    USE SIGNAL ;
    PORT
      LAYER M4 ;
        RECT  30.048 8.304 30.24 8.328 ;
    END
  END last[55]
  PIN last[56]
    DIRECTION OUTPUT ;
    USE SIGNAL ;
    PORT
      LAYER M4 ;
        RECT  30.048 8.4 30.24 8.424 ;
    END
  END last[56]
  PIN last[57]
    DIRECTION OUTPUT ;
    USE SIGNAL ;
    PORT
      LAYER M4 ;
        RECT  30.048 8.496 30.24 8.52 ;
    END
  END last[57]
  PIN last[58]
    DIRECTION OUTPUT ;
    USE SIGNAL ;
    PORT
      LAYER M4 ;
        RECT  30.048 8.592 30.24 8.616 ;
    END
  END last[58]
  PIN last[59]
    DIRECTION OUTPUT ;
    USE SIGNAL ;
    PORT
      LAYER M4 ;
        RECT  30.048 8.688 30.24 8.712 ;
    END
  END last[59]
  PIN last[5]
    DIRECTION OUTPUT ;
    USE SIGNAL ;
    PORT
      LAYER M4 ;
        RECT  30.048 3.504 30.24 3.528 ;
    END
  END last[5]
  PIN last[60]
    DIRECTION OUTPUT ;
    USE SIGNAL ;
    PORT
      LAYER M4 ;
        RECT  30.048 8.784 30.24 8.808 ;
    END
  END last[60]
  PIN last[61]
    DIRECTION OUTPUT ;
    USE SIGNAL ;
    PORT
      LAYER M4 ;
        RECT  30.048 8.88 30.24 8.904 ;
    END
  END last[61]
  PIN last[62]
    DIRECTION OUTPUT ;
    USE SIGNAL ;
    PORT
      LAYER M4 ;
        RECT  30.048 8.976 30.24 9 ;
    END
  END last[62]
  PIN last[63]
    DIRECTION OUTPUT ;
    USE SIGNAL ;
    PORT
      LAYER M4 ;
        RECT  30.048 9.072 30.24 9.096 ;
    END
  END last[63]
  PIN last[64]
    DIRECTION OUTPUT ;
    USE SIGNAL ;
    PORT
      LAYER M4 ;
        RECT  30.048 9.168 30.24 9.192 ;
    END
  END last[64]
  PIN last[65]
    DIRECTION OUTPUT ;
    USE SIGNAL ;
    PORT
      LAYER M4 ;
        RECT  30.048 9.264 30.24 9.288 ;
    END
  END last[65]
  PIN last[66]
    DIRECTION OUTPUT ;
    USE SIGNAL ;
    PORT
      LAYER M4 ;
        RECT  30.048 9.36 30.24 9.384 ;
    END
  END last[66]
  PIN last[67]
    DIRECTION OUTPUT ;
    USE SIGNAL ;
    PORT
      LAYER M4 ;
        RECT  30.048 9.456 30.24 9.48 ;
    END
  END last[67]
  PIN last[68]
    DIRECTION OUTPUT ;
    USE SIGNAL ;
    PORT
      LAYER M4 ;
        RECT  30.048 9.552 30.24 9.576 ;
    END
  END last[68]
  PIN last[69]
    DIRECTION OUTPUT ;
    USE SIGNAL ;
    PORT
      LAYER M4 ;
        RECT  30.048 9.648 30.24 9.672 ;
    END
  END last[69]
  PIN last[6]
    DIRECTION OUTPUT ;
    USE SIGNAL ;
    PORT
      LAYER M4 ;
        RECT  30.048 3.6 30.24 3.624 ;
    END
  END last[6]
  PIN last[70]
    DIRECTION OUTPUT ;
    USE SIGNAL ;
    PORT
      LAYER M4 ;
        RECT  30.048 9.744 30.24 9.768 ;
    END
  END last[70]
  PIN last[71]
    DIRECTION OUTPUT ;
    USE SIGNAL ;
    PORT
      LAYER M4 ;
        RECT  30.048 9.84 30.24 9.864 ;
    END
  END last[71]
  PIN last[72]
    DIRECTION OUTPUT ;
    USE SIGNAL ;
    PORT
      LAYER M4 ;
        RECT  30.048 9.936 30.24 9.96 ;
    END
  END last[72]
  PIN last[73]
    DIRECTION OUTPUT ;
    USE SIGNAL ;
    PORT
      LAYER M4 ;
        RECT  30.048 10.032 30.24 10.056 ;
    END
  END last[73]
  PIN last[74]
    DIRECTION OUTPUT ;
    USE SIGNAL ;
    PORT
      LAYER M4 ;
        RECT  30.048 10.128 30.24 10.152 ;
    END
  END last[74]
  PIN last[75]
    DIRECTION OUTPUT ;
    USE SIGNAL ;
    PORT
      LAYER M4 ;
        RECT  30.048 10.224 30.24 10.248 ;
    END
  END last[75]
  PIN last[76]
    DIRECTION OUTPUT ;
    USE SIGNAL ;
    PORT
      LAYER M4 ;
        RECT  30.048 10.32 30.24 10.344 ;
    END
  END last[76]
  PIN last[77]
    DIRECTION OUTPUT ;
    USE SIGNAL ;
    PORT
      LAYER M4 ;
        RECT  30.048 10.416 30.24 10.44 ;
    END
  END last[77]
  PIN last[78]
    DIRECTION OUTPUT ;
    USE SIGNAL ;
    PORT
      LAYER M4 ;
        RECT  30.048 10.512 30.24 10.536 ;
    END
  END last[78]
  PIN last[79]
    DIRECTION OUTPUT ;
    USE SIGNAL ;
    PORT
      LAYER M4 ;
        RECT  30.048 10.608 30.24 10.632 ;
    END
  END last[79]
  PIN last[7]
    DIRECTION OUTPUT ;
    USE SIGNAL ;
    PORT
      LAYER M4 ;
        RECT  30.048 3.696 30.24 3.72 ;
    END
  END last[7]
  PIN last[80]
    DIRECTION OUTPUT ;
    USE SIGNAL ;
    PORT
      LAYER M4 ;
        RECT  30.048 10.704 30.24 10.728 ;
    END
  END last[80]
  PIN last[81]
    DIRECTION OUTPUT ;
    USE SIGNAL ;
    PORT
      LAYER M4 ;
        RECT  30.048 10.8 30.24 10.824 ;
    END
  END last[81]
  PIN last[82]
    DIRECTION OUTPUT ;
    USE SIGNAL ;
    PORT
      LAYER M4 ;
        RECT  30.048 10.896 30.24 10.92 ;
    END
  END last[82]
  PIN last[83]
    DIRECTION OUTPUT ;
    USE SIGNAL ;
    PORT
      LAYER M4 ;
        RECT  30.048 10.992 30.24 11.016 ;
    END
  END last[83]
  PIN last[84]
    DIRECTION OUTPUT ;
    USE SIGNAL ;
    PORT
      LAYER M4 ;
        RECT  30.048 11.088 30.24 11.112 ;
    END
  END last[84]
  PIN last[85]
    DIRECTION OUTPUT ;
    USE SIGNAL ;
    PORT
      LAYER M4 ;
        RECT  30.048 11.184 30.24 11.208 ;
    END
  END last[85]
  PIN last[86]
    DIRECTION OUTPUT ;
    USE SIGNAL ;
    PORT
      LAYER M4 ;
        RECT  30.048 11.28 30.24 11.304 ;
    END
  END last[86]
  PIN last[87]
    DIRECTION OUTPUT ;
    USE SIGNAL ;
    PORT
      LAYER M4 ;
        RECT  30.048 11.376 30.24 11.4 ;
    END
  END last[87]
  PIN last[88]
    DIRECTION OUTPUT ;
    USE SIGNAL ;
    PORT
      LAYER M4 ;
        RECT  30.048 11.472 30.24 11.496 ;
    END
  END last[88]
  PIN last[89]
    DIRECTION OUTPUT ;
    USE SIGNAL ;
    PORT
      LAYER M4 ;
        RECT  30.048 11.568 30.24 11.592 ;
    END
  END last[89]
  PIN last[8]
    DIRECTION OUTPUT ;
    USE SIGNAL ;
    PORT
      LAYER M4 ;
        RECT  30.048 3.792 30.24 3.816 ;
    END
  END last[8]
  PIN last[90]
    DIRECTION OUTPUT ;
    USE SIGNAL ;
    PORT
      LAYER M4 ;
        RECT  30.048 11.664 30.24 11.688 ;
    END
  END last[90]
  PIN last[91]
    DIRECTION OUTPUT ;
    USE SIGNAL ;
    PORT
      LAYER M4 ;
        RECT  30.048 11.76 30.24 11.784 ;
    END
  END last[91]
  PIN last[92]
    DIRECTION OUTPUT ;
    USE SIGNAL ;
    PORT
      LAYER M4 ;
        RECT  30.048 11.856 30.24 11.88 ;
    END
  END last[92]
  PIN last[93]
    DIRECTION OUTPUT ;
    USE SIGNAL ;
    PORT
      LAYER M4 ;
        RECT  30.048 11.952 30.24 11.976 ;
    END
  END last[93]
  PIN last[94]
    DIRECTION OUTPUT ;
    USE SIGNAL ;
    PORT
      LAYER M4 ;
        RECT  30.048 12.048 30.24 12.072 ;
    END
  END last[94]
  PIN last[95]
    DIRECTION OUTPUT ;
    USE SIGNAL ;
    PORT
      LAYER M4 ;
        RECT  30.048 12.144 30.24 12.168 ;
    END
  END last[95]
  PIN last[96]
    DIRECTION OUTPUT ;
    USE SIGNAL ;
    PORT
      LAYER M4 ;
        RECT  30.048 12.24 30.24 12.264 ;
    END
  END last[96]
  PIN last[97]
    DIRECTION OUTPUT ;
    USE SIGNAL ;
    PORT
      LAYER M4 ;
        RECT  30.048 12.336 30.24 12.36 ;
    END
  END last[97]
  PIN last[98]
    DIRECTION OUTPUT ;
    USE SIGNAL ;
    PORT
      LAYER M4 ;
        RECT  30.048 12.432 30.24 12.456 ;
    END
  END last[98]
  PIN last[99]
    DIRECTION OUTPUT ;
    USE SIGNAL ;
    PORT
      LAYER M4 ;
        RECT  30.048 12.528 30.24 12.552 ;
    END
  END last[99]
  PIN last[9]
    DIRECTION OUTPUT ;
    USE SIGNAL ;
    PORT
      LAYER M4 ;
        RECT  30.048 3.888 30.24 3.912 ;
    END
  END last[9]
  PIN rst_a
    DIRECTION INPUT ;
    USE SIGNAL ;
    PORT
      LAYER M5 ;
        RECT  1.488 30.048 1.512 30.24 ;
    END
  END rst_a
  PIN VDD
    DIRECTION INOUT ;
    USE POWER ;
    PORT
      LAYER M5 ;
        RECT  24.192 2.151 24.312 28.089 ;
        RECT  18.792 2.151 18.912 28.089 ;
        RECT  13.392 2.151 13.512 28.089 ;
        RECT  7.992 2.151 8.112 28.089 ;
        RECT  2.592 2.151 2.712 28.089 ;
    END
  END VDD
  PIN VSS
    DIRECTION INOUT ;
    USE GROUND ;
    PORT
      LAYER M5 ;
        RECT  24 2.137 24.12 28.103 ;
        RECT  18.6 2.137 18.72 28.103 ;
        RECT  13.2 2.137 13.32 28.103 ;
        RECT  7.8 2.137 7.92 28.103 ;
        RECT  2.4 2.137 2.52 28.103 ;
    END
  END VSS
  # OT_OBS_CLOSED layer=M5 d_um=1.536 added=35
  OBS
    LAYER RVTN ;
     RECT  2.16 2.16 28.08 2.295 ;
     RECT  2.16 2.565 28.08 2.835 ;
     RECT  2.16 3.105 28.08 3.375 ;
     RECT  2.16 3.645 28.08 3.915 ;
     RECT  2.16 4.185 28.08 4.455 ;
     RECT  2.16 4.725 28.08 4.995 ;
     RECT  2.16 5.265 28.08 5.535 ;
     RECT  2.16 5.805 28.08 6.075 ;
     RECT  2.16 6.345 28.08 6.615 ;
     RECT  2.16 6.885 28.08 7.155 ;
     RECT  2.16 7.425 28.08 7.695 ;
     RECT  2.16 7.965 28.08 8.235 ;
     RECT  2.16 8.505 28.08 8.775 ;
     RECT  2.16 9.045 28.08 9.315 ;
     RECT  2.16 9.585 28.08 9.855 ;
     RECT  2.16 10.125 28.08 10.395 ;
     RECT  2.16 10.665 28.08 10.935 ;
     RECT  2.16 11.205 28.08 11.475 ;
     RECT  2.16 11.745 28.08 12.015 ;
     RECT  2.16 12.285 28.08 12.555 ;
     RECT  2.16 12.825 28.08 13.095 ;
     RECT  2.16 13.365 28.08 13.635 ;
     RECT  2.16 13.905 28.08 14.175 ;
     RECT  2.16 14.445 28.08 14.715 ;
     RECT  2.16 14.985 28.08 15.255 ;
     RECT  2.16 15.525 28.08 15.795 ;
     RECT  2.16 16.065 28.08 16.335 ;
     RECT  2.16 16.605 28.08 16.875 ;
     RECT  2.16 17.145 28.08 17.415 ;
     RECT  2.16 17.685 28.08 17.955 ;
     RECT  2.16 18.225 28.08 18.495 ;
     RECT  2.16 18.765 28.08 19.035 ;
     RECT  2.16 19.305 28.08 19.575 ;
     RECT  2.16 19.845 28.08 20.115 ;
     RECT  2.16 20.385 28.08 20.655 ;
     RECT  2.16 20.925 28.08 21.195 ;
     RECT  2.16 21.465 28.08 21.735 ;
     RECT  2.16 22.005 28.08 22.275 ;
     RECT  2.16 22.545 28.08 22.815 ;
     RECT  2.16 23.085 28.08 23.355 ;
     RECT  2.16 23.625 28.08 23.895 ;
     RECT  2.16 24.165 28.08 24.435 ;
     RECT  2.16 24.705 28.08 24.975 ;
     RECT  2.16 25.245 28.08 25.515 ;
     RECT  2.16 25.785 28.08 26.055 ;
     RECT  2.16 26.325 28.08 26.595 ;
     RECT  2.16 26.865 28.08 27.135 ;
     RECT  2.16 27.405 28.08 27.675 ;
     RECT  2.16 27.945 28.08 28.08 ;
    LAYER RVTP ;
     RECT  2.16 2.295 28.08 2.565 ;
     RECT  2.16 2.835 28.08 3.105 ;
     RECT  2.16 3.375 28.08 3.645 ;
     RECT  2.16 3.915 28.08 4.185 ;
     RECT  2.16 4.455 28.08 4.725 ;
     RECT  2.16 4.995 28.08 5.265 ;
     RECT  2.16 5.535 28.08 5.805 ;
     RECT  2.16 6.075 28.08 6.345 ;
     RECT  2.16 6.615 28.08 6.885 ;
     RECT  2.16 7.155 28.08 7.425 ;
     RECT  2.16 7.695 28.08 7.965 ;
     RECT  2.16 8.235 28.08 8.505 ;
     RECT  2.16 8.775 28.08 9.045 ;
     RECT  2.16 9.315 28.08 9.585 ;
     RECT  2.16 9.855 28.08 10.125 ;
     RECT  2.16 10.395 28.08 10.665 ;
     RECT  2.16 10.935 28.08 11.205 ;
     RECT  2.16 11.475 28.08 11.745 ;
     RECT  2.16 12.015 28.08 12.285 ;
     RECT  2.16 12.555 28.08 12.825 ;
     RECT  2.16 13.095 28.08 13.365 ;
     RECT  2.16 13.635 28.08 13.905 ;
     RECT  2.16 14.175 28.08 14.445 ;
     RECT  2.16 14.715 28.08 14.985 ;
     RECT  2.16 15.255 28.08 15.525 ;
     RECT  2.16 15.795 28.08 16.065 ;
     RECT  2.16 16.335 28.08 16.605 ;
     RECT  2.16 16.875 28.08 17.145 ;
     RECT  2.16 17.415 28.08 17.685 ;
     RECT  2.16 17.955 28.08 18.225 ;
     RECT  2.16 18.495 28.08 18.765 ;
     RECT  2.16 19.035 28.08 19.305 ;
     RECT  2.16 19.575 28.08 19.845 ;
     RECT  2.16 20.115 28.08 20.385 ;
     RECT  2.16 20.655 28.08 20.925 ;
     RECT  2.16 21.195 28.08 21.465 ;
     RECT  2.16 21.735 28.08 22.005 ;
     RECT  2.16 22.275 28.08 22.545 ;
     RECT  2.16 22.815 28.08 23.085 ;
     RECT  2.16 23.355 28.08 23.625 ;
     RECT  2.16 23.895 28.08 24.165 ;
     RECT  2.16 24.435 28.08 24.705 ;
     RECT  2.16 24.975 28.08 25.245 ;
     RECT  2.16 25.515 28.08 25.785 ;
     RECT  2.16 26.055 28.08 26.325 ;
     RECT  2.16 26.595 28.08 26.865 ;
     RECT  2.16 27.135 28.08 27.405 ;
     RECT  2.16 27.675 28.08 27.945 ;
    LAYER M1 ;
     RECT  2.16 2.151 28.08 28.089 ;
    LAYER M2 ;
     RECT  0.211 2.772 0.247 2.79 ;
     RECT  0.211 4.392 0.247 5.328 ;
     RECT  0.247 2.61 0.283 2.79 ;
     RECT  0.247 4.392 0.283 5.796 ;
     RECT  0.283 4.158 0.319 6.03 ;
     RECT  0.211 6.822 0.319 6.912 ;
     RECT  0.283 2.61 0.499 3.168 ;
     RECT  0.319 4.158 0.499 6.912 ;
     RECT  0.499 2.61 0.535 6.912 ;
     RECT  1.723 15.462 1.867 15.48 ;
     RECT  0.535 2.61 2.16 7.416 ;
     RECT  0.211 8.316 2.16 9.036 ;
     RECT  0.211 12.33 2.16 12.348 ;
     RECT  1.723 14.652 2.16 14.67 ;
     RECT  1.867 15.462 2.16 15.858 ;
     RECT  1.399 17.892 2.16 17.91 ;
     RECT  2.16 2.151 2.839 28.089 ;
     RECT  2.839 2.034 4.271 28.089 ;
     RECT  4.567 29.034 4.667 29.052 ;
     RECT  4.271 2.106 4.847 28.089 ;
     RECT  4.847 2.151 21.451 28.089 ;
     RECT  21.451 1.998 24.331 28.089 ;
     RECT  24.331 1.881 26.807 28.089 ;
     RECT  26.807 1.962 28.08 28.089 ;
     RECT  28.08 3.96 28.103 19.332 ;
     RECT  28.103 3.96 28.175 19.296 ;
     RECT  28.175 3.96 28.535 18.414 ;
     RECT  28.535 4.23 28.571 18.414 ;
     RECT  28.175 19.278 28.823 19.296 ;
     RECT  28.571 4.356 28.967 18.414 ;
     RECT  28.967 4.356 29.039 18.144 ;
     RECT  28.08 1.962 29.111 3.204 ;
     RECT  29.039 4.356 29.111 15.624 ;
     RECT  29.111 1.962 29.147 3.132 ;
     RECT  29.111 4.356 29.147 15.552 ;
     RECT  29.147 1.962 29.183 2.754 ;
     RECT  29.147 5.274 29.183 15.552 ;
     RECT  29.183 2.034 29.219 2.754 ;
     RECT  29.219 2.304 29.255 2.754 ;
     RECT  29.039 16.416 29.399 18.144 ;
     RECT  29.147 4.356 29.651 4.482 ;
     RECT  29.183 5.274 29.651 6.642 ;
     RECT  29.183 7.704 29.651 15.552 ;
     RECT  29.651 4.464 29.687 4.482 ;
     RECT  29.651 5.274 29.687 5.292 ;
     RECT  29.651 6.246 29.687 6.642 ;
     RECT  29.651 7.704 29.687 9.648 ;
     RECT  29.651 10.746 29.723 11.538 ;
     RECT  29.651 12.834 29.723 15.552 ;
     RECT  29.687 8.316 29.759 8.334 ;
     RECT  29.723 11.214 29.759 11.232 ;
     RECT  29.723 12.834 29.759 13.968 ;
     RECT  29.723 14.796 29.759 15.552 ;
     RECT  29.759 15.534 29.795 15.552 ;
     RECT  29.759 13.266 29.867 13.968 ;
     RECT  29.399 16.506 29.939 18.144 ;
     RECT  29.939 17.496 29.975 18.144 ;
     RECT  29.255 2.736 29.983 2.754 ;
     RECT  29.975 17.496 30.011 17.514 ;
     RECT  29.867 13.266 30.047 13.284 ;
     RECT  29.939 16.506 30.047 16.524 ;
     RECT  29.983 2.736 30.083 2.862 ;
    LAYER M3 ;
     RECT  25.92 1.957 25.938 1.993 ;
     RECT  26.784 1.876 26.802 1.993 ;
     RECT  25.92 1.993 26.802 2.029 ;
     RECT  29.16 1.957 29.178 2.029 ;
     RECT  24.336 1.876 24.354 2.065 ;
     RECT  25.668 2.029 26.802 2.065 ;
     RECT  29.16 2.029 29.214 2.065 ;
     RECT  4.248 2.029 4.266 2.101 ;
     RECT  2.844 2.029 2.862 2.143 ;
     RECT  24.336 2.065 26.802 2.143 ;
     RECT  2.415 2.143 2.862 2.191 ;
     RECT  3.96 2.101 4.842 2.191 ;
     RECT  24.015 2.143 26.802 2.191 ;
     RECT  29.088 2.065 29.214 2.299 ;
     RECT  24.015 2.191 27.702 2.335 ;
     RECT  29.088 2.299 29.25 2.371 ;
     RECT  7.815 2.143 7.905 2.413 ;
     RECT  13.215 2.143 13.305 2.413 ;
     RECT  18.615 2.143 18.705 2.413 ;
     RECT  19.512 2.263 19.53 2.413 ;
     RECT  2.415 2.191 4.842 2.461 ;
     RECT  6.516 2.371 6.534 2.461 ;
     RECT  21.456 1.993 21.474 2.533 ;
     RECT  24.015 2.335 27.99 2.569 ;
     RECT  28.764 2.371 29.25 2.569 ;
     RECT  7.815 2.413 8.097 2.605 ;
     RECT  20.952 2.533 21.474 2.605 ;
     RECT  2.415 2.461 5.13 2.641 ;
     RECT  5.94 2.461 6.534 2.641 ;
     RECT  10.944 2.191 10.962 2.641 ;
     RECT  16.38 2.605 16.398 2.641 ;
     RECT  24.015 2.569 29.25 2.641 ;
     RECT  13.215 2.413 13.497 2.725 ;
     RECT  13.215 2.725 13.554 2.731 ;
     RECT  18.615 2.413 19.53 2.731 ;
     RECT  2.415 2.641 6.93 2.759 ;
     RECT  0.252 2.605 0.27 2.767 ;
     RECT  16.164 2.641 16.398 2.767 ;
     RECT  10.296 2.641 10.962 2.795 ;
     RECT  13.215 2.731 13.698 2.795 ;
     RECT  0.216 2.767 0.27 2.803 ;
     RECT  9.54 2.731 9.558 2.803 ;
     RECT  10.296 2.795 10.926 2.803 ;
     RECT  20.952 2.605 21.834 2.803 ;
     RECT  13.215 2.795 13.626 2.831 ;
     RECT  30.06 2.731 30.078 2.839 ;
     RECT  29.988 2.839 30.078 2.867 ;
     RECT  14.832 2.569 15.39 2.875 ;
     RECT  18.468 2.731 19.53 2.875 ;
     RECT  9.54 2.803 10.926 2.911 ;
     RECT  18.468 2.875 20.07 2.911 ;
     RECT  20.952 2.803 22.518 2.911 ;
     RECT  14.796 2.875 15.39 3.001 ;
     RECT  16.164 2.767 16.83 3.001 ;
     RECT  2.415 2.759 6.39 3.019 ;
     RECT  9.468 2.911 10.926 3.029 ;
     RECT  7.815 2.605 8.586 3.065 ;
     RECT  9.54 3.029 10.926 3.065 ;
     RECT  14.796 3.001 16.83 3.101 ;
     RECT  2.304 3.019 6.39 3.211 ;
     RECT  14.832 3.101 16.83 3.299 ;
     RECT  2.268 3.211 6.39 3.335 ;
     RECT  9.684 3.065 10.926 3.335 ;
     RECT  0.216 2.803 0.342 3.341 ;
     RECT  0.252 3.341 0.342 3.379 ;
     RECT  16.74 3.299 16.83 3.415 ;
     RECT  17.676 2.731 17.694 3.415 ;
     RECT  23.904 2.641 29.25 3.451 ;
     RECT  0.252 3.379 0.558 3.533 ;
     RECT  10.836 3.335 10.926 3.541 ;
     RECT  14.832 3.299 15.426 3.569 ;
     RECT  7.815 3.065 8.55 3.649 ;
     RECT  13.215 2.831 13.497 3.649 ;
     RECT  23.76 3.451 29.25 3.649 ;
     RECT  10.836 3.541 11.106 3.677 ;
     RECT  18.468 2.911 22.518 3.685 ;
     RECT  23.4 3.649 29.25 3.685 ;
     RECT  2.304 3.335 6.39 3.721 ;
     RECT  10.836 3.677 11.034 3.839 ;
     RECT  14.832 3.569 15.102 3.883 ;
     RECT  18.468 3.685 29.25 3.917 ;
     RECT  2.304 3.721 6.498 3.955 ;
     RECT  2.304 3.955 6.642 3.991 ;
     RECT  7.416 3.649 8.55 3.991 ;
     RECT  0.288 3.533 0.558 4.109 ;
     RECT  16.74 3.415 17.694 4.153 ;
     RECT  18.468 3.917 28.782 4.153 ;
     RECT  2.304 3.991 8.55 4.253 ;
     RECT  16.74 4.153 28.782 4.253 ;
     RECT  10.836 3.839 10.854 4.261 ;
     RECT  14.544 3.883 15.102 4.261 ;
     RECT  16.74 4.253 28.026 4.261 ;
     RECT  29.988 2.867 30.006 4.267 ;
     RECT  0.288 4.109 0.522 4.301 ;
     RECT  0.288 4.301 0.414 4.387 ;
     RECT  14.508 4.261 15.102 4.387 ;
     RECT  15.984 4.261 28.026 4.387 ;
     RECT  29.628 4.267 30.006 4.397 ;
     RECT  13.215 3.649 13.662 4.423 ;
     RECT  13.215 4.423 13.698 4.459 ;
     RECT  14.508 4.387 28.026 4.459 ;
     RECT  13.215 4.459 28.026 4.496 ;
     RECT  10.62 4.261 10.854 4.657 ;
     RECT  0.216 4.387 0.414 4.685 ;
     RECT  13.215 4.496 19.71 4.685 ;
     RECT  28.764 4.253 28.782 4.685 ;
     RECT  10.62 4.657 10.962 4.693 ;
     RECT  10.62 4.693 11.034 4.729 ;
     RECT  29.628 4.397 29.682 4.729 ;
     RECT  9.684 3.335 9.702 4.793 ;
     RECT  13.215 4.685 13.497 4.801 ;
     RECT  2.304 4.253 8.334 4.991 ;
     RECT  10.62 4.729 11.142 4.991 ;
     RECT  2.304 4.991 8.262 5.027 ;
     RECT  11.232 4.999 11.43 5.071 ;
     RECT  11.232 5.071 12.042 5.197 ;
     RECT  14.256 4.685 19.71 5.225 ;
     RECT  14.328 5.225 19.71 5.233 ;
     RECT  20.448 4.496 28.026 5.233 ;
     RECT  11.232 5.197 12.114 5.269 ;
     RECT  14.328 5.233 28.026 5.333 ;
     RECT  11.232 5.269 12.222 5.369 ;
     RECT  14.328 5.333 27.99 5.459 ;
     RECT  0.216 4.685 0.342 5.503 ;
     RECT  0.216 5.503 0.558 5.741 ;
     RECT  2.304 5.027 8.097 5.809 ;
     RECT  10.26 5.431 10.314 5.881 ;
     RECT  2.304 5.809 8.334 5.899 ;
     RECT  2.268 5.899 8.334 5.909 ;
     RECT  11.232 5.369 11.934 5.909 ;
     RECT  9.648 5.881 10.314 5.999 ;
     RECT  9.792 5.999 10.314 6.035 ;
     RECT  11.232 5.909 11.538 6.035 ;
     RECT  11.232 6.035 11.466 6.043 ;
     RECT  14.652 5.459 27.99 6.079 ;
     RECT  29.088 4.729 29.682 6.079 ;
     RECT  14.652 6.079 29.682 6.305 ;
     RECT  13.104 4.801 13.497 6.385 ;
     RECT  10.764 6.043 11.466 6.539 ;
     RECT  16.488 6.305 29.682 6.701 ;
     RECT  16.488 6.701 29.178 6.809 ;
     RECT  2.268 5.909 8.154 6.817 ;
     RECT  12.456 6.385 13.497 6.845 ;
     RECT  16.488 6.809 19.422 6.845 ;
     RECT  13.215 6.845 13.497 6.889 ;
     RECT  14.652 6.305 15.534 6.889 ;
     RECT  0.216 5.741 0.342 6.917 ;
     RECT  2.232 6.817 8.154 6.917 ;
     RECT  9.792 6.035 9.81 6.925 ;
     RECT  0.324 6.917 0.342 6.989 ;
     RECT  20.16 6.809 29.178 6.989 ;
     RECT  2.304 6.917 8.154 7.087 ;
     RECT  13.215 6.889 15.534 7.115 ;
     RECT  20.916 6.989 29.178 7.115 ;
     RECT  9.792 6.925 9.99 7.123 ;
     RECT  2.304 7.087 8.694 7.187 ;
     RECT  10.836 6.539 11.466 7.195 ;
     RECT  9.756 7.123 9.99 7.223 ;
     RECT  20.988 7.115 29.178 7.223 ;
     RECT  14.4 7.115 15.534 7.231 ;
     RECT  16.488 6.845 19.17 7.231 ;
     RECT  2.304 7.187 8.586 7.349 ;
     RECT  10.836 7.195 12.222 7.349 ;
     RECT  10.836 7.349 11.574 7.429 ;
     RECT  0.54 7.393 0.558 7.469 ;
     RECT  9.828 7.223 9.99 7.501 ;
     RECT  10.8 7.429 11.574 7.501 ;
     RECT  14.4 7.231 19.17 7.529 ;
     RECT  21.024 7.223 29.178 7.531 ;
     RECT  14.832 7.529 19.17 7.619 ;
     RECT  16.308 7.619 19.17 7.663 ;
     RECT  20.16 6.989 20.178 7.663 ;
     RECT  21.024 7.531 29.682 7.799 ;
     RECT  9.828 7.501 11.574 7.889 ;
     RECT  9.9 7.889 11.574 7.925 ;
     RECT  16.308 7.663 20.178 7.963 ;
     RECT  21.024 7.799 27.954 7.963 ;
     RECT  10.584 7.925 11.574 7.997 ;
     RECT  2.304 7.349 8.19 8.107 ;
     RECT  14.832 7.619 15.426 8.275 ;
     RECT  0.252 8.299 0.27 8.311 ;
     RECT  29.088 7.799 29.682 8.311 ;
     RECT  10.728 7.997 11.574 8.339 ;
     RECT  13.215 7.115 13.497 8.401 ;
     RECT  14.544 8.275 15.426 8.401 ;
     RECT  16.308 7.963 27.954 8.401 ;
     RECT  14.544 8.401 27.954 8.429 ;
     RECT  2.268 8.107 8.19 8.437 ;
     RECT  10.764 8.339 11.574 8.581 ;
     RECT  29.088 8.311 29.754 8.621 ;
     RECT  14.544 8.429 21.114 8.671 ;
     RECT  0.216 8.311 0.27 8.683 ;
     RECT  22.212 8.429 27.954 8.683 ;
     RECT  29.088 8.621 29.682 8.683 ;
     RECT  2.268 8.437 8.262 8.699 ;
     RECT  13.104 8.401 13.497 8.743 ;
     RECT  14.256 8.671 21.114 8.771 ;
     RECT  0.216 8.683 0.414 8.813 ;
     RECT  12.708 8.743 13.497 8.815 ;
     RECT  14.256 8.771 19.242 8.815 ;
     RECT  10.764 8.581 11.682 8.879 ;
     RECT  9.648 8.671 9.666 9.049 ;
     RECT  22.212 8.683 29.682 9.101 ;
     RECT  9.648 9.049 9.702 9.121 ;
     RECT  10.764 8.879 11.646 9.121 ;
     RECT  9.648 9.121 11.646 9.239 ;
     RECT  20.232 8.771 21.114 9.349 ;
     RECT  28.476 9.101 29.682 9.389 ;
     RECT  10.764 9.239 11.646 9.419 ;
     RECT  9.648 9.239 10.026 9.545 ;
     RECT  12.708 8.815 19.242 9.553 ;
     RECT  20.232 9.349 21.438 9.553 ;
     RECT  22.212 9.101 27.738 9.553 ;
     RECT  28.548 9.389 29.682 9.581 ;
     RECT  2.268 8.699 8.097 9.589 ;
     RECT  12.708 9.553 27.738 9.617 ;
     RECT  12.708 9.617 27.702 9.625 ;
     RECT  12.564 9.625 27.702 9.653 ;
     RECT  2.232 9.589 8.097 9.677 ;
     RECT  11.628 9.419 11.646 9.689 ;
     RECT  0.216 8.813 0.234 9.773 ;
     RECT  12.564 9.653 19.17 9.779 ;
     RECT  19.908 9.653 27.702 9.779 ;
     RECT  17.46 9.779 19.17 9.815 ;
     RECT  2.268 9.677 8.097 9.823 ;
     RECT  8.82 9.211 8.838 9.823 ;
     RECT  2.268 9.823 8.838 9.895 ;
     RECT  9.648 9.545 9.846 9.895 ;
     RECT  20.988 9.779 21.762 9.959 ;
     RECT  10.836 9.419 10.854 10.291 ;
     RECT  12.564 9.779 16.722 10.291 ;
     RECT  29.052 9.581 29.682 10.315 ;
     RECT  10.8 10.291 10.854 10.399 ;
     RECT  17.496 9.815 19.17 10.399 ;
     RECT  19.908 9.779 20.178 10.399 ;
     RECT  29.052 10.315 29.718 10.411 ;
     RECT  12.204 10.291 16.722 10.435 ;
     RECT  10.8 10.399 11.034 10.471 ;
     RECT  28.512 10.411 29.718 10.499 ;
     RECT  29.088 10.499 29.718 10.507 ;
     RECT  2.268 9.895 9.846 10.603 ;
     RECT  10.764 10.471 11.034 10.603 ;
     RECT  21.096 9.959 21.762 10.633 ;
     RECT  22.5 9.779 27.702 10.633 ;
     RECT  12.024 10.435 16.722 10.669 ;
     RECT  17.496 10.399 20.178 10.669 ;
     RECT  21.096 10.633 27.702 10.696 ;
     RECT  20.952 10.696 27.702 10.699 ;
     RECT  12.024 10.669 20.178 10.795 ;
     RECT  20.952 10.699 28.026 10.795 ;
     RECT  12.024 10.795 28.026 10.829 ;
     RECT  2.268 10.603 11.034 10.967 ;
     RECT  29.088 10.507 29.754 10.987 ;
     RECT  12.024 10.829 20.538 11.003 ;
     RECT  13.104 11.003 20.538 11.039 ;
     RECT  2.304 10.967 11.034 11.131 ;
     RECT  13.104 11.039 15.822 11.165 ;
     RECT  21.672 10.829 28.026 11.165 ;
     RECT  21.672 11.165 21.762 11.237 ;
     RECT  22.644 11.165 28.026 11.245 ;
     RECT  29.088 10.987 30.042 11.245 ;
     RECT  0.252 11.131 0.27 11.309 ;
     RECT  22.644 11.245 30.042 11.405 ;
     RECT  2.304 11.131 11.178 11.407 ;
     RECT  12.024 11.003 12.258 11.407 ;
     RECT  13.104 11.165 15.534 11.705 ;
     RECT  21.672 11.237 21.69 11.705 ;
     RECT  16.56 11.039 20.538 11.749 ;
     RECT  16.56 11.749 20.61 11.821 ;
     RECT  22.644 11.405 28.026 11.849 ;
     RECT  13.104 11.705 13.698 11.939 ;
     RECT  2.304 11.407 12.258 11.947 ;
     RECT  13.104 11.939 13.662 11.947 ;
     RECT  2.304 11.947 13.662 11.975 ;
     RECT  16.524 11.821 20.61 11.983 ;
     RECT  22.644 11.849 27.738 11.983 ;
     RECT  22.536 11.983 27.738 12.055 ;
     RECT  14.544 11.705 15.534 12.091 ;
     RECT  16.524 11.983 21.546 12.091 ;
     RECT  10.584 11.975 13.662 12.119 ;
     RECT  16.416 12.091 21.546 12.209 ;
     RECT  22.464 12.055 27.738 12.209 ;
     RECT  14.544 12.091 15.642 12.325 ;
     RECT  16.416 12.209 20.79 12.325 ;
     RECT  2.304 11.975 9.846 12.331 ;
     RECT  29.052 11.405 30.042 12.331 ;
     RECT  0.216 12.325 0.234 12.427 ;
     RECT  21.528 12.209 21.546 12.523 ;
     RECT  0.216 12.427 0.414 12.557 ;
     RECT  21.528 12.523 21.726 12.631 ;
     RECT  22.716 12.209 27.738 12.715 ;
     RECT  28.512 12.331 30.042 12.715 ;
     RECT  10.584 12.119 12.114 12.749 ;
     RECT  21.528 12.631 21.87 12.749 ;
     RECT  22.716 12.715 30.042 12.749 ;
     RECT  14.544 12.325 20.79 12.785 ;
     RECT  13.215 12.119 13.662 12.829 ;
     RECT  2.232 12.331 9.846 12.901 ;
     RECT  10.584 12.749 12.078 12.901 ;
     RECT  15.048 12.785 20.79 13.055 ;
     RECT  17.388 13.055 20.79 13.099 ;
     RECT  21.528 12.749 21.726 13.099 ;
     RECT  17.388 13.099 21.726 13.127 ;
     RECT  17.388 13.127 21.51 13.289 ;
     RECT  22.788 12.749 30.042 13.289 ;
     RECT  13.215 12.829 13.698 13.441 ;
     RECT  15.048 13.055 16.65 13.469 ;
     RECT  13.215 13.441 13.734 13.603 ;
     RECT  13.104 13.603 13.734 13.739 ;
     RECT  2.232 12.901 12.078 13.771 ;
     RECT  15.048 13.469 16.578 13.837 ;
     RECT  13.14 13.739 13.734 13.873 ;
     RECT  14.832 13.837 16.578 13.873 ;
     RECT  0.252 13.723 0.27 13.901 ;
     RECT  13.14 13.873 16.578 13.901 ;
     RECT  22.788 13.289 29.862 13.945 ;
     RECT  22.428 13.945 29.862 14.099 ;
     RECT  1.98 13.771 12.078 14.155 ;
     RECT  23.004 14.099 29.862 14.155 ;
     RECT  1.728 14.155 12.078 14.251 ;
     RECT  13.215 13.901 16.578 14.251 ;
     RECT  13.215 14.251 16.614 14.521 ;
     RECT  17.388 13.289 21.366 14.521 ;
     RECT  13.215 14.521 21.366 14.711 ;
     RECT  13.215 14.711 16.65 14.747 ;
     RECT  1.404 14.251 12.078 14.791 ;
     RECT  13.215 14.747 15.21 14.791 ;
     RECT  17.388 14.711 21.366 14.791 ;
     RECT  1.404 14.791 15.21 14.909 ;
     RECT  0.396 14.827 0.414 14.923 ;
     RECT  23.004 14.155 30.006 14.923 ;
     RECT  17.388 14.791 21.474 14.945 ;
     RECT  15.984 14.747 16.65 15.089 ;
     RECT  17.82 14.945 21.474 15.179 ;
     RECT  23.004 14.923 30.042 15.187 ;
     RECT  0.288 14.923 0.414 15.211 ;
     RECT  0.216 15.211 0.414 15.245 ;
     RECT  0.216 15.245 0.234 15.389 ;
     RECT  16.56 15.089 16.65 15.457 ;
     RECT  22.896 15.187 30.042 15.529 ;
     RECT  22.86 15.529 30.042 15.565 ;
     RECT  22.716 15.565 30.042 15.719 ;
     RECT  1.404 14.909 13.914 15.835 ;
     RECT  14.688 14.909 15.21 15.835 ;
     RECT  1.404 15.835 15.21 15.863 ;
     RECT  22.716 15.719 23.058 15.979 ;
     RECT  16.56 15.457 17.082 15.989 ;
     RECT  17.892 15.179 21.474 15.997 ;
     RECT  17.46 15.997 21.474 16.097 ;
     RECT  22.248 15.979 23.058 16.259 ;
     RECT  22.716 16.259 23.058 16.331 ;
     RECT  2.34 15.863 15.21 16.363 ;
     RECT  17.532 16.097 21.474 16.411 ;
     RECT  23.904 15.719 30.042 16.439 ;
     RECT  22.824 16.331 23.058 16.501 ;
     RECT  23.904 16.439 28.962 16.501 ;
     RECT  17.532 16.411 21.69 16.529 ;
     RECT  29.916 16.439 30.042 16.529 ;
     RECT  19.656 16.529 21.042 16.673 ;
     RECT  17.532 16.529 18.897 16.709 ;
     RECT  2.34 16.363 15.498 16.799 ;
     RECT  17.532 16.709 17.55 16.799 ;
     RECT  16.272 16.141 16.362 16.871 ;
     RECT  20.088 16.673 21.042 16.907 ;
     RECT  2.376 16.799 15.498 16.943 ;
     RECT  20.124 16.907 21.042 16.979 ;
     RECT  22.824 16.501 28.962 16.979 ;
     RECT  29.916 16.529 30.006 16.979 ;
     RECT  2.376 16.943 14.67 17.069 ;
     RECT  16.272 16.871 16.29 17.339 ;
     RECT  20.124 16.979 20.142 17.339 ;
     RECT  23.364 16.979 28.962 17.339 ;
     RECT  18.615 16.709 18.897 17.491 ;
     RECT  29.952 16.979 30.006 17.519 ;
     RECT  18.615 17.491 19.206 17.609 ;
     RECT  23.364 17.339 24.297 17.609 ;
     RECT  21.024 16.979 21.042 17.789 ;
     RECT  1.404 15.863 1.422 17.915 ;
     RECT  29.952 17.519 29.97 18.149 ;
     RECT  2.376 17.069 14.562 18.419 ;
     RECT  25.02 17.339 28.962 18.419 ;
     RECT  2.415 18.419 14.562 18.463 ;
     RECT  15.48 16.943 15.498 18.463 ;
     RECT  2.415 18.463 15.498 18.841 ;
     RECT  25.02 18.419 28.818 19.067 ;
     RECT  2.415 18.841 15.894 19.111 ;
     RECT  25.02 19.067 25.434 19.265 ;
     RECT  26.604 19.067 28.818 19.265 ;
     RECT  28.08 19.265 28.818 19.301 ;
     RECT  28.08 19.301 28.098 19.337 ;
     RECT  2.415 19.111 15.93 19.381 ;
     RECT  25.02 19.265 25.29 19.499 ;
     RECT  26.604 19.265 27.162 19.499 ;
     RECT  25.02 19.499 25.038 19.679 ;
     RECT  2.415 19.381 16.002 21.001 ;
     RECT  2.34 21.001 16.002 23.701 ;
     RECT  2.34 23.701 16.146 24.241 ;
     RECT  2.268 24.241 16.146 24.935 ;
     RECT  2.268 24.935 16.11 25.979 ;
     RECT  2.268 25.979 16.074 26.905 ;
     RECT  2.268 26.905 16.11 27.095 ;
     RECT  2.304 27.095 16.11 27.599 ;
     RECT  18.615 17.609 18.897 27.827 ;
     RECT  24.015 17.609 24.297 27.827 ;
     RECT  2.304 27.599 15.93 27.869 ;
     RECT  2.304 27.869 15.606 27.965 ;
     RECT  2.304 27.965 15.39 28.013 ;
     RECT  2.304 28.013 15.354 28.097 ;
     RECT  18.615 27.827 18.705 28.097 ;
     RECT  24.015 27.827 24.105 28.097 ;
     RECT  3.132 28.097 15.354 28.493 ;
     RECT  3.132 28.493 15.138 28.541 ;
     RECT  8.748 28.541 11.394 28.589 ;
     RECT  11.052 28.589 11.394 29.021 ;
     RECT  3.132 28.541 6.57 29.069 ;
     RECT  11.052 29.021 11.286 29.069 ;
     RECT  12.276 28.541 13.122 29.069 ;
     RECT  2.304 28.097 2.322 29.117 ;
     RECT  8.748 28.589 10.206 29.117 ;
     RECT  11.052 29.069 11.25 29.117 ;
     RECT  8.748 29.117 9.882 29.165 ;
     RECT  11.232 29.117 11.25 29.165 ;
     RECT  3.996 29.069 6.57 29.693 ;
     RECT  7.596 28.541 7.974 29.693 ;
     RECT  8.748 29.165 9.234 29.693 ;
     RECT  12.564 29.069 12.762 29.693 ;
     RECT  13.86 28.541 15.138 29.693 ;
     RECT  4.068 29.693 4.086 29.741 ;
     RECT  5.652 29.693 6.318 29.741 ;
     RECT  7.956 29.693 7.974 29.741 ;
     RECT  12.564 29.693 12.582 29.741 ;
     RECT  5.76 29.741 5.958 29.789 ;
     RECT  5.76 29.789 5.778 30.125 ;
    LAYER M4 ;
     RECT  0.156 3.024 0.181 15.24 ;
     RECT  0.181 3.024 0.205 15.336 ;
     RECT  1.477 29.088 2.333 29.112 ;
     RECT  0.205 3.024 2.408 15.384 ;
     RECT  2.408 2.148 2.512 28.092 ;
     RECT  2.512 2.418 2.704 28.092 ;
     RECT  2.704 2.736 2.729 6.12 ;
     RECT  2.704 25.44 2.765 25.464 ;
     RECT  2.729 2.736 2.819 5.544 ;
     RECT  2.819 2.832 2.837 5.544 ;
     RECT  2.704 20.832 2.845 21.72 ;
     RECT  2.845 20.832 2.945 21.672 ;
     RECT  2.704 10.128 2.981 17.112 ;
     RECT  2.704 27.84 3.077 28.092 ;
     RECT  2.837 2.832 3.125 5.112 ;
     RECT  2.704 22.848 3.125 23.88 ;
     RECT  3.077 27.84 3.388 29.064 ;
     RECT  3.388 27.84 3.413 28.056 ;
     RECT  2.704 18.192 3.733 19.656 ;
     RECT  2.945 20.832 3.733 21.144 ;
     RECT  2.704 26.736 3.769 26.76 ;
     RECT  3.413 27.84 3.769 28.008 ;
     RECT  3.388 29.04 3.772 29.064 ;
     RECT  3.769 26.736 3.781 28.008 ;
     RECT  2.704 7.872 3.913 9.144 ;
     RECT  3.733 18.192 3.925 21.144 ;
     RECT  3.125 22.848 3.925 23.832 ;
     RECT  3.125 4.512 3.949 5.112 ;
     RECT  3.769 6.336 3.949 6.36 ;
     RECT  3.913 7.44 3.949 9.144 ;
     RECT  2.981 10.176 3.949 17.112 ;
     RECT  3.973 29.664 4.028 29.688 ;
     RECT  4.028 29.664 4.115 29.736 ;
     RECT  3.949 4.512 4.22 6.36 ;
     RECT  3.125 2.832 4.261 3.24 ;
     RECT  4.22 4.368 4.261 6.36 ;
     RECT  3.925 18.192 4.261 21.384 ;
     RECT  3.925 22.704 4.261 23.832 ;
     RECT  4.261 2.832 4.307 6.36 ;
     RECT  3.949 7.44 4.412 17.112 ;
     RECT  4.261 18.192 4.412 23.832 ;
     RECT  3.769 25.104 4.421 25.128 ;
     RECT  3.781 26.448 4.453 28.008 ;
     RECT  4.453 25.68 4.517 28.008 ;
     RECT  4.517 25.68 4.565 28.488 ;
     RECT  4.307 2.88 4.597 6.36 ;
     RECT  4.412 7.44 4.597 23.832 ;
     RECT  4.565 26.832 4.741 28.488 ;
     RECT  4.115 29.664 4.741 29.688 ;
     RECT  4.741 26.832 4.853 29.688 ;
     RECT  4.597 2.88 4.877 23.832 ;
     RECT  4.877 2.88 4.961 24.12 ;
     RECT  4.853 29.664 5.413 29.688 ;
     RECT  4.961 2.88 5.609 23.832 ;
     RECT  4.853 26.832 5.651 28.68 ;
     RECT  5.413 29.664 5.701 29.736 ;
     RECT  4.565 25.68 5.749 25.704 ;
     RECT  5.651 26.832 5.749 28.056 ;
     RECT  5.701 29.664 5.749 30.024 ;
     RECT  5.749 29.664 5.833 30.12 ;
     RECT  5.749 25.68 5.921 28.056 ;
     RECT  5.833 29.664 6.035 29.784 ;
     RECT  5.609 3.216 6.083 23.832 ;
     RECT  6.035 29.664 6.145 29.736 ;
     RECT  6.083 12.768 6.172 23.832 ;
     RECT  6.145 29.088 6.323 29.736 ;
     RECT  6.172 12.768 6.329 14.952 ;
     RECT  6.172 15.984 6.389 23.832 ;
     RECT  5.921 24.912 6.389 28.056 ;
     RECT  6.083 3.216 6.419 11.784 ;
     RECT  6.323 29.664 6.515 29.736 ;
     RECT  6.389 15.984 6.661 28.056 ;
     RECT  6.419 3.84 6.761 11.784 ;
     RECT  6.515 29.664 7.621 29.688 ;
     RECT  6.761 3.84 7.808 6.888 ;
     RECT  6.761 7.872 7.808 11.784 ;
     RECT  6.329 12.768 7.808 14.52 ;
     RECT  6.661 15.984 7.808 28.536 ;
     RECT  7.808 2.148 7.912 28.536 ;
     RECT  7.621 29.664 7.985 29.736 ;
     RECT  7.912 2.418 8.104 28.536 ;
     RECT  8.104 18 8.245 26.232 ;
     RECT  8.104 27.36 8.387 28.536 ;
     RECT  8.245 18 8.561 25.896 ;
     RECT  8.387 27.36 8.561 28.056 ;
     RECT  7.985 29.664 8.677 29.688 ;
     RECT  8.561 27.36 8.705 27.96 ;
     RECT  8.561 25.104 9.137 25.896 ;
     RECT  8.561 18 9.173 23.928 ;
     RECT  9.173 18 9.281 22.872 ;
     RECT  8.677 29.088 9.299 29.688 ;
     RECT  9.281 22.752 9.461 22.872 ;
     RECT  8.705 27.936 9.541 27.96 ;
     RECT  9.493 26.784 9.577 26.808 ;
     RECT  9.541 27.936 9.677 28.056 ;
     RECT  9.281 18 9.713 21.48 ;
     RECT  9.299 29.088 9.916 29.16 ;
     RECT  9.677 28.032 9.925 28.056 ;
     RECT  9.916 29.088 9.925 29.112 ;
     RECT  9.713 18 9.929 21.432 ;
     RECT  9.137 25.104 10.253 25.128 ;
     RECT  8.104 9.264 10.433 11.688 ;
     RECT  10.433 11.136 10.681 11.688 ;
     RECT  8.104 12.768 10.681 14.52 ;
     RECT  9.925 28.032 10.693 29.112 ;
     RECT  10.693 27.936 10.837 29.112 ;
     RECT  9.929 18.672 10.865 21.432 ;
     RECT  8.104 3.84 10.973 4.728 ;
     RECT  10.837 28.992 10.981 29.112 ;
     RECT  10.357 25.584 11.077 25.896 ;
     RECT  9.173 23.904 11.18 23.928 ;
     RECT  10.681 11.136 11.189 14.52 ;
     RECT  11.189 11.664 11.261 14.52 ;
     RECT  10.981 28.992 11.261 29.16 ;
     RECT  8.104 15.984 11.365 16.968 ;
     RECT  11.077 25.584 11.365 26.232 ;
     RECT  11.261 11.664 11.369 11.88 ;
     RECT  11.365 25.584 11.461 26.76 ;
     RECT  10.837 27.936 11.461 27.96 ;
     RECT  10.865 18.768 11.617 21.432 ;
     RECT  9.461 22.8 11.617 22.872 ;
     RECT  11.261 13.536 11.699 14.52 ;
     RECT  11.617 18.768 11.701 22.872 ;
     RECT  11.365 15.792 11.765 16.968 ;
     RECT  11.461 25.584 11.833 27.96 ;
     RECT  11.833 25.536 11.9 27.96 ;
     RECT  11.261 28.992 11.9 29.064 ;
     RECT  11.9 25.536 11.987 29.064 ;
     RECT  11.369 11.664 12.089 11.688 ;
     RECT  11.18 23.904 12.121 24.552 ;
     RECT  11.987 25.536 12.121 25.752 ;
     RECT  11.987 26.784 12.553 29.064 ;
     RECT  11.701 18.768 12.757 21.528 ;
     RECT  11.701 22.56 12.757 22.872 ;
     RECT  12.757 18.768 12.908 22.872 ;
     RECT  12.121 23.904 12.908 25.752 ;
     RECT  12.553 26.784 12.947 29.736 ;
     RECT  11.699 13.872 13.093 14.52 ;
     RECT  10.973 3.84 13.208 3.864 ;
     RECT  10.433 9.264 13.208 9.816 ;
     RECT  13.093 13.68 13.208 14.52 ;
     RECT  11.765 15.792 13.208 16.92 ;
     RECT  12.908 18.768 13.208 25.752 ;
     RECT  12.947 26.784 13.208 29.688 ;
     RECT  13.208 2.148 13.312 29.688 ;
     RECT  13.312 2.418 13.504 29.688 ;
     RECT  13.504 13.68 13.667 14.52 ;
     RECT  13.504 20.88 13.667 23.928 ;
     RECT  13.504 26.16 13.708 29.688 ;
     RECT  13.504 2.736 13.709 2.76 ;
     RECT  13.504 15.696 13.709 16.824 ;
     RECT  13.667 21.12 13.709 22.824 ;
     RECT  13.709 21.12 13.715 22.248 ;
     RECT  13.504 25.056 13.889 25.176 ;
     RECT  13.667 14.496 13.925 14.52 ;
     RECT  13.715 21.12 13.961 21.144 ;
     RECT  13.504 18.672 13.997 19.8 ;
     RECT  13.889 25.056 13.997 25.08 ;
     RECT  13.715 22.224 14.033 22.248 ;
     RECT  13.504 8.976 14.069 9.864 ;
     RECT  14.069 8.976 14.14 9.816 ;
     RECT  13.997 18.672 14.141 19.032 ;
     RECT  13.708 26.208 14.177 29.688 ;
     RECT  14.141 18.768 14.213 19.032 ;
     RECT  14.177 26.208 14.213 28.536 ;
     RECT  14.213 26.208 14.62 26.232 ;
     RECT  14.213 27.312 14.645 28.536 ;
     RECT  13.504 3.84 14.821 3.864 ;
     RECT  14.821 3.84 14.861 3.96 ;
     RECT  14.213 18.768 14.969 18.792 ;
     RECT  14.14 9.072 15.041 9.816 ;
     RECT  14.177 29.664 15.149 29.688 ;
     RECT  14.645 27.936 15.251 28.536 ;
     RECT  15.251 27.936 15.365 28.488 ;
     RECT  13.667 23.904 15.401 23.928 ;
     RECT  15.365 27.936 15.401 28.008 ;
     RECT  14.533 11.808 15.509 11.832 ;
     RECT  13.709 15.696 15.509 16.392 ;
     RECT  15.401 27.936 15.617 27.96 ;
     RECT  15.041 9.744 15.869 9.816 ;
     RECT  16.405 13.104 16.508 13.128 ;
     RECT  14.861 3.936 16.549 3.96 ;
     RECT  16.508 12.528 16.549 13.128 ;
     RECT  16.549 11.952 16.595 13.128 ;
     RECT  16.549 3.936 16.873 4.536 ;
     RECT  16.729 10.848 17.057 10.872 ;
     RECT  16.873 3.936 17.089 5.016 ;
     RECT  16.081 6 17.089 6.024 ;
     RECT  17.089 7.776 17.125 7.8 ;
     RECT  15.869 9.792 17.125 9.816 ;
     RECT  16.595 13.008 17.237 13.032 ;
     RECT  16.595 11.952 17.269 11.976 ;
     RECT  15.509 15.696 17.377 15.72 ;
     RECT  17.089 3.936 17.509 6.024 ;
     RECT  17.509 3.696 17.596 6.024 ;
     RECT  17.269 11.184 17.597 11.976 ;
     RECT  17.596 3.936 17.665 6.024 ;
     RECT  17.665 3.936 17.881 6.264 ;
     RECT  17.125 7.776 17.881 9.816 ;
     RECT  17.597 11.184 18.229 11.4 ;
     RECT  17.881 3.936 18.601 9.816 ;
     RECT  18.601 3.84 18.608 9.816 ;
     RECT  18.229 11.136 18.608 11.4 ;
     RECT  17.377 14.832 18.608 15.72 ;
     RECT  18.608 2.148 18.712 28.092 ;
     RECT  18.712 2.418 18.904 27.822 ;
     RECT  18.904 9.072 18.965 9.336 ;
     RECT  18.904 14.736 19.037 15.72 ;
     RECT  18.904 11.136 19.523 11.4 ;
     RECT  18.904 12.72 19.564 12.744 ;
     RECT  18.904 3.84 19.613 6.312 ;
     RECT  19.523 11.136 19.897 11.16 ;
     RECT  19.613 4.464 19.933 6.312 ;
     RECT  19.933 4.464 20.117 6.456 ;
     RECT  18.904 13.728 20.261 13.752 ;
     RECT  18.904 7.44 20.365 7.992 ;
     RECT  20.365 7.44 20.473 8.088 ;
     RECT  19.897 11.088 20.509 11.16 ;
     RECT  20.117 4.512 20.513 6.456 ;
     RECT  19.037 14.832 20.549 15.72 ;
     RECT  20.513 4.512 20.585 5.208 ;
     RECT  20.549 15.312 20.621 15.72 ;
     RECT  20.401 12.912 20.765 12.936 ;
     RECT  20.509 10.8 20.941 11.16 ;
     RECT  20.473 7.44 21.049 8.328 ;
     RECT  18.965 9.312 21.049 9.336 ;
     RECT  20.513 6.24 21.061 6.456 ;
     RECT  21.049 7.44 21.061 9.336 ;
     RECT  21.061 6.24 21.409 9.336 ;
     RECT  21.409 6.24 21.665 9.384 ;
     RECT  18.904 2.736 21.697 2.76 ;
     RECT  20.585 4.752 21.697 5.208 ;
     RECT  21.665 6.384 21.733 9.384 ;
     RECT  20.941 10.704 21.733 11.16 ;
     RECT  21.733 6.384 21.773 11.16 ;
     RECT  21.773 6.576 22.097 11.16 ;
     RECT  20.621 15.312 22.237 15.336 ;
     RECT  21.697 2.736 22.421 5.208 ;
     RECT  21.517 12.528 22.777 12.552 ;
     RECT  22.777 12.528 22.813 12.888 ;
     RECT  22.237 15.312 22.835 16.008 ;
     RECT  22.097 6.576 22.961 10.728 ;
     RECT  22.813 12.528 22.981 13.656 ;
     RECT  22.421 4.464 23.173 5.208 ;
     RECT  22.981 12.48 23.857 13.656 ;
     RECT  23.173 4.464 24.001 5.592 ;
     RECT  22.961 6.576 24.001 8.328 ;
     RECT  22.421 2.736 24.008 2.76 ;
     RECT  24.001 4.464 24.008 8.328 ;
     RECT  22.961 9.312 24.008 10.728 ;
     RECT  23.857 11.76 24.008 13.656 ;
     RECT  22.835 15.312 24.008 15.432 ;
     RECT  24.008 2.148 24.112 28.092 ;
     RECT  24.112 2.418 24.304 27.822 ;
     RECT  24.304 9.312 24.581 14.232 ;
     RECT  24.304 8.16 25.013 8.184 ;
     RECT  24.304 2.64 25.369 7.128 ;
     RECT  24.581 9.312 25.585 12.072 ;
     RECT  24.581 13.632 25.585 14.232 ;
     RECT  25.585 9.312 25.769 14.232 ;
     RECT  25.769 9.312 26.057 13.752 ;
     RECT  26.057 9.312 26.161 11.736 ;
     RECT  25.369 2.208 26.197 7.128 ;
     RECT  26.161 8.4 26.197 11.736 ;
     RECT  26.197 2.208 26.201 11.736 ;
     RECT  26.201 2.64 26.345 11.736 ;
     RECT  25.801 15.936 26.381 15.96 ;
     RECT  26.345 9.744 26.417 11.736 ;
     RECT  26.057 12.72 26.705 13.752 ;
     RECT  26.557 14.784 26.705 14.808 ;
     RECT  26.705 12.912 26.773 13.752 ;
     RECT  26.773 12.912 26.813 14.04 ;
     RECT  26.417 10.896 26.921 11.736 ;
     RECT  26.701 15.888 27.137 15.912 ;
     RECT  26.921 10.896 27.209 11.4 ;
     RECT  26.417 9.744 27.385 9.864 ;
     RECT  27.209 10.896 27.385 11.112 ;
     RECT  27.385 9.744 27.493 11.112 ;
     RECT  26.345 2.64 27.497 8.424 ;
     RECT  27.497 2.64 27.605 7.464 ;
     RECT  27.605 2.736 27.749 7.464 ;
     RECT  27.493 9.456 27.925 11.112 ;
     RECT  27.925 12.72 27.961 12.744 ;
     RECT  26.813 13.728 27.961 14.04 ;
     RECT  27.961 12.72 27.997 14.04 ;
     RECT  27.925 9.072 28.465 11.112 ;
     RECT  27.749 3.024 28.501 7.464 ;
     RECT  28.465 8.688 28.501 11.112 ;
     RECT  27.997 12.72 28.501 14.472 ;
     RECT  28.501 3.024 28.789 14.472 ;
     RECT  28.789 3.024 30.06 15.24 ;
    LAYER M5 ;
     RECT  2.4 2.137 2.52 2.151 ;
     RECT  7.8 2.137 7.92 2.151 ;
     RECT  13.2 2.137 13.32 2.151 ;
     RECT  18.6 2.137 18.72 2.151 ;
     RECT  24 2.137 24.12 2.151 ;
     RECT  2.4 2.151 2.712 2.725 ;
     RECT  4.272 2.821 4.296 2.869 ;
     RECT  3.84 2.869 4.296 3.397 ;
     RECT  2.4 2.725 2.808 3.829 ;
     RECT  0.288 3.733 0.312 3.923 ;
     RECT  3.84 3.397 4.872 3.973 ;
     RECT  2.4 3.829 2.856 4.501 ;
     RECT  3.84 3.973 4.92 4.501 ;
     RECT  17.52 3.685 17.544 4.691 ;
     RECT  6.384 3.205 6.408 4.739 ;
     RECT  2.4 4.501 4.92 4.789 ;
     RECT  18.6 2.151 18.912 4.789 ;
     RECT  18.6 4.789 19.512 5.363 ;
     RECT  2.4 4.789 4.968 5.893 ;
     RECT  18.6 5.363 18.912 7.429 ;
     RECT  21.072 5.077 21.096 7.475 ;
     RECT  7.8 2.151 8.112 7.909 ;
     RECT  2.4 5.893 5.064 8.197 ;
     RECT  6.048 5.077 6.072 8.197 ;
     RECT  2.4 8.197 6.072 8.485 ;
     RECT  13.2 2.151 13.512 8.965 ;
     RECT  7.488 7.909 8.112 9.061 ;
     RECT  2.4 8.485 6.264 9.109 ;
     RECT  7.44 9.061 8.112 9.109 ;
     RECT  2.4 9.109 8.112 9.251 ;
     RECT  13.2 8.965 14.088 9.731 ;
     RECT  2.4 9.251 6.072 10.453 ;
     RECT  7.44 9.251 8.112 10.453 ;
     RECT  2.4 10.453 8.112 10.885 ;
     RECT  18.24 7.429 18.912 11.171 ;
     RECT  18.6 11.171 18.912 11.365 ;
     RECT  18.6 11.365 19.512 12.755 ;
     RECT  16.56 12.517 16.584 13.139 ;
     RECT  22.992 12.469 23.016 13.379 ;
     RECT  2.4 10.885 8.808 13.621 ;
     RECT  13.2 9.731 13.656 13.669 ;
     RECT  13.104 13.669 13.656 13.715 ;
     RECT  2.304 13.621 8.808 13.811 ;
     RECT  2.304 13.811 6.36 15.011 ;
     RECT  1.008 13.861 1.032 15.013 ;
     RECT  0.192 15.013 1.032 15.347 ;
     RECT  11.664 13.525 11.688 15.781 ;
     RECT  13.104 13.715 13.512 15.973 ;
     RECT  22.8 15.301 22.824 16.019 ;
     RECT  13.104 15.973 13.608 16.643 ;
     RECT  11.376 15.781 11.688 16.741 ;
     RECT  2.4 15.011 6.36 18.181 ;
     RECT  7.44 13.811 8.808 18.181 ;
     RECT  10.992 16.741 11.688 20.003 ;
     RECT  2.4 18.181 8.808 20.725 ;
     RECT  13.2 16.643 13.608 20.869 ;
     RECT  2.4 20.725 9.528 21.155 ;
     RECT  13.2 20.869 13.656 21.493 ;
     RECT  13.2 21.493 13.704 21.637 ;
     RECT  11.664 20.003 11.688 22.259 ;
     RECT  12.768 21.637 13.704 22.259 ;
     RECT  12.768 22.259 13.656 22.549 ;
     RECT  9.504 21.155 9.528 22.741 ;
     RECT  2.4 21.155 8.112 22.835 ;
     RECT  4.944 22.835 8.112 22.931 ;
     RECT  2.4 22.835 3.912 22.979 ;
     RECT  12.528 22.549 13.656 23.651 ;
     RECT  2.4 22.979 3.336 23.843 ;
     RECT  5.04 22.931 8.112 24.085 ;
     RECT  4.896 24.085 8.112 24.421 ;
     RECT  4.896 24.421 8.232 24.469 ;
     RECT  9.408 22.741 9.528 24.469 ;
     RECT  12.528 23.651 13.512 24.469 ;
     RECT  11.952 24.469 13.512 24.517 ;
     RECT  4.896 24.469 9.528 25.093 ;
     RECT  4.896 25.093 9.672 25.573 ;
     RECT  11.232 24.517 13.512 25.573 ;
     RECT  4.896 25.573 13.512 25.861 ;
     RECT  4.464 25.861 13.512 26.149 ;
     RECT  4.464 26.149 13.656 26.197 ;
     RECT  4.464 26.197 14.568 26.437 ;
     RECT  2.4 23.843 2.712 26.725 ;
     RECT  3.792 26.437 14.568 26.725 ;
     RECT  2.4 26.725 14.568 27.925 ;
     RECT  18.6 12.755 18.912 28.089 ;
     RECT  24 2.151 24.312 28.089 ;
     RECT  2.4 27.925 14.952 28.103 ;
     RECT  18.6 28.089 18.72 28.103 ;
     RECT  24 28.089 24.12 28.103 ;
     RECT  3.024 28.103 14.952 28.453 ;
     RECT  3.024 28.453 15.144 28.501 ;
     RECT  1.008 15.347 1.032 29.077 ;
     RECT  1.008 29.077 1.512 30.096 ;
     RECT  3.024 28.501 15.24 30.096 ;
     RECT  5.76 30.096 5.784 30.131 ;
     RECT  2.808 2.821 4.272 2.869 ;
     RECT  2.808 2.869 3.84 3.829 ;
     RECT  6.408 3.205 7.8 4.739 ;
     RECT  4.872 3.397 6.384 3.973 ;
     RECT  17.544 3.685 18.6 4.691 ;
     RECT  2.856 3.829 3.84 4.501 ;
     RECT  4.92 3.973 6.384 4.739 ;
     RECT  4.92 4.739 6.072 4.789 ;
     RECT  4.968 4.789 6.072 5.077 ;
     RECT  4.968 5.077 6.048 5.893 ;
     RECT  5.064 5.893 6.048 8.197 ;
     RECT  6.072 7.909 7.488 8.485 ;
     RECT  6.264 8.485 7.488 9.061 ;
     RECT  6.264 9.061 7.44 9.109 ;
     RECT  6.072 9.251 7.44 10.453 ;
     RECT  23.016 12.469 24 13.379 ;
     RECT  11.688 13.525 13.2 13.669 ;
     RECT  11.688 13.669 13.104 16.643 ;
     RECT  6.36 13.811 7.44 18.181 ;
     RECT  1.032 13.861 2.304 15.011 ;
     RECT  1.032 15.011 2.4 28.103 ;
     RECT  22.824 15.301 24 16.019 ;
     RECT  11.688 16.643 13.2 21.637 ;
     RECT  8.112 21.155 9.504 22.741 ;
     RECT  11.688 21.637 12.768 22.259 ;
     RECT  12.528 22.259 12.768 22.549 ;
     RECT  8.112 22.741 9.408 24.421 ;
     RECT  3.912 22.835 4.944 22.931 ;
     RECT  3.912 22.931 5.04 22.979 ;
     RECT  4.896 22.979 5.04 24.085 ;
     RECT  8.232 24.421 9.408 24.469 ;
     RECT  2.712 26.437 3.792 26.725 ;
     RECT  1.032 28.103 3.024 29.077 ;
     RECT  1.512 29.077 3.024 30 ;
     RECT  1.56 30 2.976 30.096 ;
  END
END ot_smh_tr_w128_s2_m80
END LIBRARY
